VERSION 5.8 ;
BUSBITCHARS "[]" ;
DIVIDERCHAR "/" ;
UNITS
    DATABASE MICRONS 1000 ;
END UNITS

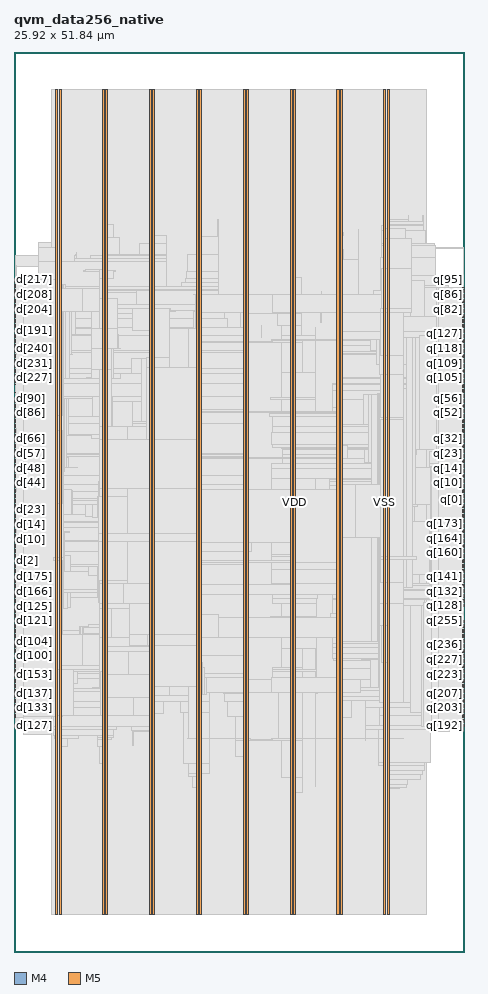
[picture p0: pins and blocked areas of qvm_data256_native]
MACRO qvm_data256_native
  FOREIGN qvm_data256_native 0 0 ;
  CLASS BLOCK ;
  SIZE 25.92 BY 51.84 ;
  PIN clk
    DIRECTION INPUT ;
    USE SIGNAL ;
    PORT
      LAYER M4 ;
        RECT  0 22.704 0.084 22.728 ;
    END
  END clk
  PIN d[0]
    DIRECTION INPUT ;
    USE SIGNAL ;
    PORT
      LAYER M4 ;
        RECT  0 22.8 0.084 22.824 ;
    END
  END d[0]
  PIN d[100]
    DIRECTION INPUT ;
    USE SIGNAL ;
    PORT
      LAYER M4 ;
        RECT  0 17.04 0.084 17.064 ;
    END
  END d[100]
  PIN d[101]
    DIRECTION INPUT ;
    USE SIGNAL ;
    PORT
      LAYER M4 ;
        RECT  0 17.136 0.084 17.16 ;
    END
  END d[101]
  PIN d[102]
    DIRECTION INPUT ;
    USE SIGNAL ;
    PORT
      LAYER M4 ;
        RECT  0 17.232 0.084 17.256 ;
    END
  END d[102]
  PIN d[103]
    DIRECTION INPUT ;
    USE SIGNAL ;
    PORT
      LAYER M4 ;
        RECT  0 17.328 0.084 17.352 ;
    END
  END d[103]
  PIN d[104]
    DIRECTION INPUT ;
    USE SIGNAL ;
    PORT
      LAYER M4 ;
        RECT  0 17.424 0.084 17.448 ;
    END
  END d[104]
  PIN d[105]
    DIRECTION INPUT ;
    USE SIGNAL ;
    PORT
      LAYER M4 ;
        RECT  0 17.52 0.084 17.544 ;
    END
  END d[105]
  PIN d[106]
    DIRECTION INPUT ;
    USE SIGNAL ;
    PORT
      LAYER M4 ;
        RECT  0 17.616 0.084 17.64 ;
    END
  END d[106]
  PIN d[107]
    DIRECTION INPUT ;
    USE SIGNAL ;
    PORT
      LAYER M4 ;
        RECT  0 17.712 0.084 17.736 ;
    END
  END d[107]
  PIN d[108]
    DIRECTION INPUT ;
    USE SIGNAL ;
    PORT
      LAYER M4 ;
        RECT  0 17.808 0.084 17.832 ;
    END
  END d[108]
  PIN d[109]
    DIRECTION INPUT ;
    USE SIGNAL ;
    PORT
      LAYER M4 ;
        RECT  0 17.904 0.084 17.928 ;
    END
  END d[109]
  PIN d[10]
    DIRECTION INPUT ;
    USE SIGNAL ;
    PORT
      LAYER M4 ;
        RECT  0 23.76 0.084 23.784 ;
    END
  END d[10]
  PIN d[110]
    DIRECTION INPUT ;
    USE SIGNAL ;
    PORT
      LAYER M4 ;
        RECT  0 18 0.084 18.024 ;
    END
  END d[110]
  PIN d[111]
    DIRECTION INPUT ;
    USE SIGNAL ;
    PORT
      LAYER M4 ;
        RECT  0 18.096 0.084 18.12 ;
    END
  END d[111]
  PIN d[112]
    DIRECTION INPUT ;
    USE SIGNAL ;
    PORT
      LAYER M4 ;
        RECT  0 18.192 0.084 18.216 ;
    END
  END d[112]
  PIN d[113]
    DIRECTION INPUT ;
    USE SIGNAL ;
    PORT
      LAYER M4 ;
        RECT  0 18.288 0.084 18.312 ;
    END
  END d[113]
  PIN d[114]
    DIRECTION INPUT ;
    USE SIGNAL ;
    PORT
      LAYER M4 ;
        RECT  0 18.384 0.084 18.408 ;
    END
  END d[114]
  PIN d[115]
    DIRECTION INPUT ;
    USE SIGNAL ;
    PORT
      LAYER M4 ;
        RECT  0 18.48 0.084 18.504 ;
    END
  END d[115]
  PIN d[116]
    DIRECTION INPUT ;
    USE SIGNAL ;
    PORT
      LAYER M4 ;
        RECT  0 18.576 0.084 18.6 ;
    END
  END d[116]
  PIN d[117]
    DIRECTION INPUT ;
    USE SIGNAL ;
    PORT
      LAYER M4 ;
        RECT  0 18.672 0.084 18.696 ;
    END
  END d[117]
  PIN d[118]
    DIRECTION INPUT ;
    USE SIGNAL ;
    PORT
      LAYER M4 ;
        RECT  0 18.768 0.084 18.792 ;
    END
  END d[118]
  PIN d[119]
    DIRECTION INPUT ;
    USE SIGNAL ;
    PORT
      LAYER M4 ;
        RECT  0 18.864 0.084 18.888 ;
    END
  END d[119]
  PIN d[11]
    DIRECTION INPUT ;
    USE SIGNAL ;
    PORT
      LAYER M4 ;
        RECT  0 23.856 0.084 23.88 ;
    END
  END d[11]
  PIN d[120]
    DIRECTION INPUT ;
    USE SIGNAL ;
    PORT
      LAYER M4 ;
        RECT  0 18.96 0.084 18.984 ;
    END
  END d[120]
  PIN d[121]
    DIRECTION INPUT ;
    USE SIGNAL ;
    PORT
      LAYER M4 ;
        RECT  0 19.056 0.084 19.08 ;
    END
  END d[121]
  PIN d[122]
    DIRECTION INPUT ;
    USE SIGNAL ;
    PORT
      LAYER M4 ;
        RECT  0 19.152 0.084 19.176 ;
    END
  END d[122]
  PIN d[123]
    DIRECTION INPUT ;
    USE SIGNAL ;
    PORT
      LAYER M4 ;
        RECT  0 19.248 0.084 19.272 ;
    END
  END d[123]
  PIN d[124]
    DIRECTION INPUT ;
    USE SIGNAL ;
    PORT
      LAYER M4 ;
        RECT  0 19.344 0.084 19.368 ;
    END
  END d[124]
  PIN d[125]
    DIRECTION INPUT ;
    USE SIGNAL ;
    PORT
      LAYER M4 ;
        RECT  0 19.44 0.084 19.464 ;
    END
  END d[125]
  PIN d[126]
    DIRECTION INPUT ;
    USE SIGNAL ;
    PORT
      LAYER M4 ;
        RECT  0 19.536 0.084 19.56 ;
    END
  END d[126]
  PIN d[127]
    DIRECTION INPUT ;
    USE SIGNAL ;
    PORT
      LAYER M4 ;
        RECT  0 13.488 0.084 13.512 ;
    END
  END d[127]
  PIN d[128]
    DIRECTION INPUT ;
    USE SIGNAL ;
    PORT
      LAYER M4 ;
        RECT  0 13.584 0.084 13.608 ;
    END
  END d[128]
  PIN d[129]
    DIRECTION INPUT ;
    USE SIGNAL ;
    PORT
      LAYER M4 ;
        RECT  0 13.68 0.084 13.704 ;
    END
  END d[129]
  PIN d[12]
    DIRECTION INPUT ;
    USE SIGNAL ;
    PORT
      LAYER M4 ;
        RECT  0 23.952 0.084 23.976 ;
    END
  END d[12]
  PIN d[130]
    DIRECTION INPUT ;
    USE SIGNAL ;
    PORT
      LAYER M4 ;
        RECT  0 13.776 0.084 13.8 ;
    END
  END d[130]
  PIN d[131]
    DIRECTION INPUT ;
    USE SIGNAL ;
    PORT
      LAYER M4 ;
        RECT  0 13.872 0.084 13.896 ;
    END
  END d[131]
  PIN d[132]
    DIRECTION INPUT ;
    USE SIGNAL ;
    PORT
      LAYER M4 ;
        RECT  0 13.968 0.084 13.992 ;
    END
  END d[132]
  PIN d[133]
    DIRECTION INPUT ;
    USE SIGNAL ;
    PORT
      LAYER M4 ;
        RECT  0 14.064 0.084 14.088 ;
    END
  END d[133]
  PIN d[134]
    DIRECTION INPUT ;
    USE SIGNAL ;
    PORT
      LAYER M4 ;
        RECT  0 14.16 0.084 14.184 ;
    END
  END d[134]
  PIN d[135]
    DIRECTION INPUT ;
    USE SIGNAL ;
    PORT
      LAYER M4 ;
        RECT  0 14.256 0.084 14.28 ;
    END
  END d[135]
  PIN d[136]
    DIRECTION INPUT ;
    USE SIGNAL ;
    PORT
      LAYER M4 ;
        RECT  0 14.352 0.084 14.376 ;
    END
  END d[136]
  PIN d[137]
    DIRECTION INPUT ;
    USE SIGNAL ;
    PORT
      LAYER M4 ;
        RECT  0 14.448 0.084 14.472 ;
    END
  END d[137]
  PIN d[138]
    DIRECTION INPUT ;
    USE SIGNAL ;
    PORT
      LAYER M4 ;
        RECT  0 14.544 0.084 14.568 ;
    END
  END d[138]
  PIN d[139]
    DIRECTION INPUT ;
    USE SIGNAL ;
    PORT
      LAYER M4 ;
        RECT  0 14.64 0.084 14.664 ;
    END
  END d[139]
  PIN d[13]
    DIRECTION INPUT ;
    USE SIGNAL ;
    PORT
      LAYER M4 ;
        RECT  0 24.048 0.084 24.072 ;
    END
  END d[13]
  PIN d[140]
    DIRECTION INPUT ;
    USE SIGNAL ;
    PORT
      LAYER M4 ;
        RECT  0 14.736 0.084 14.76 ;
    END
  END d[140]
  PIN d[141]
    DIRECTION INPUT ;
    USE SIGNAL ;
    PORT
      LAYER M4 ;
        RECT  0 14.832 0.084 14.856 ;
    END
  END d[141]
  PIN d[142]
    DIRECTION INPUT ;
    USE SIGNAL ;
    PORT
      LAYER M4 ;
        RECT  0 14.928 0.084 14.952 ;
    END
  END d[142]
  PIN d[143]
    DIRECTION INPUT ;
    USE SIGNAL ;
    PORT
      LAYER M4 ;
        RECT  0 15.024 0.084 15.048 ;
    END
  END d[143]
  PIN d[144]
    DIRECTION INPUT ;
    USE SIGNAL ;
    PORT
      LAYER M4 ;
        RECT  0 15.12 0.084 15.144 ;
    END
  END d[144]
  PIN d[145]
    DIRECTION INPUT ;
    USE SIGNAL ;
    PORT
      LAYER M4 ;
        RECT  0 15.216 0.084 15.24 ;
    END
  END d[145]
  PIN d[146]
    DIRECTION INPUT ;
    USE SIGNAL ;
    PORT
      LAYER M4 ;
        RECT  0 15.312 0.084 15.336 ;
    END
  END d[146]
  PIN d[147]
    DIRECTION INPUT ;
    USE SIGNAL ;
    PORT
      LAYER M4 ;
        RECT  0 15.408 0.084 15.432 ;
    END
  END d[147]
  PIN d[148]
    DIRECTION INPUT ;
    USE SIGNAL ;
    PORT
      LAYER M4 ;
        RECT  0 15.504 0.084 15.528 ;
    END
  END d[148]
  PIN d[149]
    DIRECTION INPUT ;
    USE SIGNAL ;
    PORT
      LAYER M4 ;
        RECT  0 15.6 0.084 15.624 ;
    END
  END d[149]
  PIN d[14]
    DIRECTION INPUT ;
    USE SIGNAL ;
    PORT
      LAYER M4 ;
        RECT  0 24.144 0.084 24.168 ;
    END
  END d[14]
  PIN d[150]
    DIRECTION INPUT ;
    USE SIGNAL ;
    PORT
      LAYER M4 ;
        RECT  0 15.696 0.084 15.72 ;
    END
  END d[150]
  PIN d[151]
    DIRECTION INPUT ;
    USE SIGNAL ;
    PORT
      LAYER M4 ;
        RECT  0 15.792 0.084 15.816 ;
    END
  END d[151]
  PIN d[152]
    DIRECTION INPUT ;
    USE SIGNAL ;
    PORT
      LAYER M4 ;
        RECT  0 15.888 0.084 15.912 ;
    END
  END d[152]
  PIN d[153]
    DIRECTION INPUT ;
    USE SIGNAL ;
    PORT
      LAYER M4 ;
        RECT  0 15.984 0.084 16.008 ;
    END
  END d[153]
  PIN d[154]
    DIRECTION INPUT ;
    USE SIGNAL ;
    PORT
      LAYER M4 ;
        RECT  0 16.08 0.084 16.104 ;
    END
  END d[154]
  PIN d[155]
    DIRECTION INPUT ;
    USE SIGNAL ;
    PORT
      LAYER M4 ;
        RECT  0 16.176 0.084 16.2 ;
    END
  END d[155]
  PIN d[156]
    DIRECTION INPUT ;
    USE SIGNAL ;
    PORT
      LAYER M4 ;
        RECT  0 16.272 0.084 16.296 ;
    END
  END d[156]
  PIN d[157]
    DIRECTION INPUT ;
    USE SIGNAL ;
    PORT
      LAYER M4 ;
        RECT  0 16.368 0.084 16.392 ;
    END
  END d[157]
  PIN d[158]
    DIRECTION INPUT ;
    USE SIGNAL ;
    PORT
      LAYER M4 ;
        RECT  0 16.464 0.084 16.488 ;
    END
  END d[158]
  PIN d[159]
    DIRECTION INPUT ;
    USE SIGNAL ;
    PORT
      LAYER M4 ;
        RECT  0 19.632 0.084 19.656 ;
    END
  END d[159]
  PIN d[15]
    DIRECTION INPUT ;
    USE SIGNAL ;
    PORT
      LAYER M4 ;
        RECT  0 24.24 0.084 24.264 ;
    END
  END d[15]
  PIN d[160]
    DIRECTION INPUT ;
    USE SIGNAL ;
    PORT
      LAYER M4 ;
        RECT  0 19.728 0.084 19.752 ;
    END
  END d[160]
  PIN d[161]
    DIRECTION INPUT ;
    USE SIGNAL ;
    PORT
      LAYER M4 ;
        RECT  0 19.824 0.084 19.848 ;
    END
  END d[161]
  PIN d[162]
    DIRECTION INPUT ;
    USE SIGNAL ;
    PORT
      LAYER M4 ;
        RECT  0 19.92 0.084 19.944 ;
    END
  END d[162]
  PIN d[163]
    DIRECTION INPUT ;
    USE SIGNAL ;
    PORT
      LAYER M4 ;
        RECT  0 20.016 0.084 20.04 ;
    END
  END d[163]
  PIN d[164]
    DIRECTION INPUT ;
    USE SIGNAL ;
    PORT
      LAYER M4 ;
        RECT  0 20.112 0.084 20.136 ;
    END
  END d[164]
  PIN d[165]
    DIRECTION INPUT ;
    USE SIGNAL ;
    PORT
      LAYER M4 ;
        RECT  0 20.208 0.084 20.232 ;
    END
  END d[165]
  PIN d[166]
    DIRECTION INPUT ;
    USE SIGNAL ;
    PORT
      LAYER M4 ;
        RECT  0 20.304 0.084 20.328 ;
    END
  END d[166]
  PIN d[167]
    DIRECTION INPUT ;
    USE SIGNAL ;
    PORT
      LAYER M4 ;
        RECT  0 20.4 0.084 20.424 ;
    END
  END d[167]
  PIN d[168]
    DIRECTION INPUT ;
    USE SIGNAL ;
    PORT
      LAYER M4 ;
        RECT  0 20.496 0.084 20.52 ;
    END
  END d[168]
  PIN d[169]
    DIRECTION INPUT ;
    USE SIGNAL ;
    PORT
      LAYER M4 ;
        RECT  0 20.592 0.084 20.616 ;
    END
  END d[169]
  PIN d[16]
    DIRECTION INPUT ;
    USE SIGNAL ;
    PORT
      LAYER M4 ;
        RECT  0 24.336 0.084 24.36 ;
    END
  END d[16]
  PIN d[170]
    DIRECTION INPUT ;
    USE SIGNAL ;
    PORT
      LAYER M4 ;
        RECT  0 20.688 0.084 20.712 ;
    END
  END d[170]
  PIN d[171]
    DIRECTION INPUT ;
    USE SIGNAL ;
    PORT
      LAYER M4 ;
        RECT  0 20.784 0.084 20.808 ;
    END
  END d[171]
  PIN d[172]
    DIRECTION INPUT ;
    USE SIGNAL ;
    PORT
      LAYER M4 ;
        RECT  0 20.88 0.084 20.904 ;
    END
  END d[172]
  PIN d[173]
    DIRECTION INPUT ;
    USE SIGNAL ;
    PORT
      LAYER M4 ;
        RECT  0 20.976 0.084 21 ;
    END
  END d[173]
  PIN d[174]
    DIRECTION INPUT ;
    USE SIGNAL ;
    PORT
      LAYER M4 ;
        RECT  0 21.072 0.084 21.096 ;
    END
  END d[174]
  PIN d[175]
    DIRECTION INPUT ;
    USE SIGNAL ;
    PORT
      LAYER M4 ;
        RECT  0 21.168 0.084 21.192 ;
    END
  END d[175]
  PIN d[176]
    DIRECTION INPUT ;
    USE SIGNAL ;
    PORT
      LAYER M4 ;
        RECT  0 21.264 0.084 21.288 ;
    END
  END d[176]
  PIN d[177]
    DIRECTION INPUT ;
    USE SIGNAL ;
    PORT
      LAYER M4 ;
        RECT  0 21.36 0.084 21.384 ;
    END
  END d[177]
  PIN d[178]
    DIRECTION INPUT ;
    USE SIGNAL ;
    PORT
      LAYER M4 ;
        RECT  0 21.456 0.084 21.48 ;
    END
  END d[178]
  PIN d[179]
    DIRECTION INPUT ;
    USE SIGNAL ;
    PORT
      LAYER M4 ;
        RECT  0 21.552 0.084 21.576 ;
    END
  END d[179]
  PIN d[17]
    DIRECTION INPUT ;
    USE SIGNAL ;
    PORT
      LAYER M4 ;
        RECT  0 24.432 0.084 24.456 ;
    END
  END d[17]
  PIN d[180]
    DIRECTION INPUT ;
    USE SIGNAL ;
    PORT
      LAYER M4 ;
        RECT  0 21.648 0.084 21.672 ;
    END
  END d[180]
  PIN d[181]
    DIRECTION INPUT ;
    USE SIGNAL ;
    PORT
      LAYER M4 ;
        RECT  0 21.744 0.084 21.768 ;
    END
  END d[181]
  PIN d[182]
    DIRECTION INPUT ;
    USE SIGNAL ;
    PORT
      LAYER M4 ;
        RECT  0 21.84 0.084 21.864 ;
    END
  END d[182]
  PIN d[183]
    DIRECTION INPUT ;
    USE SIGNAL ;
    PORT
      LAYER M4 ;
        RECT  0 21.936 0.084 21.96 ;
    END
  END d[183]
  PIN d[184]
    DIRECTION INPUT ;
    USE SIGNAL ;
    PORT
      LAYER M4 ;
        RECT  0 22.032 0.084 22.056 ;
    END
  END d[184]
  PIN d[185]
    DIRECTION INPUT ;
    USE SIGNAL ;
    PORT
      LAYER M4 ;
        RECT  0 22.128 0.084 22.152 ;
    END
  END d[185]
  PIN d[186]
    DIRECTION INPUT ;
    USE SIGNAL ;
    PORT
      LAYER M4 ;
        RECT  0 22.224 0.084 22.248 ;
    END
  END d[186]
  PIN d[187]
    DIRECTION INPUT ;
    USE SIGNAL ;
    PORT
      LAYER M4 ;
        RECT  0 22.32 0.084 22.344 ;
    END
  END d[187]
  PIN d[188]
    DIRECTION INPUT ;
    USE SIGNAL ;
    PORT
      LAYER M4 ;
        RECT  0 22.416 0.084 22.44 ;
    END
  END d[188]
  PIN d[189]
    DIRECTION INPUT ;
    USE SIGNAL ;
    PORT
      LAYER M4 ;
        RECT  0 22.512 0.084 22.536 ;
    END
  END d[189]
  PIN d[18]
    DIRECTION INPUT ;
    USE SIGNAL ;
    PORT
      LAYER M4 ;
        RECT  0 24.528 0.084 24.552 ;
    END
  END d[18]
  PIN d[190]
    DIRECTION INPUT ;
    USE SIGNAL ;
    PORT
      LAYER M4 ;
        RECT  0 22.608 0.084 22.632 ;
    END
  END d[190]
  PIN d[191]
    DIRECTION INPUT ;
    USE SIGNAL ;
    PORT
      LAYER M4 ;
        RECT  0 35.76 0.084 35.784 ;
    END
  END d[191]
  PIN d[192]
    DIRECTION INPUT ;
    USE SIGNAL ;
    PORT
      LAYER M4 ;
        RECT  0 35.856 0.084 35.88 ;
    END
  END d[192]
  PIN d[193]
    DIRECTION INPUT ;
    USE SIGNAL ;
    PORT
      LAYER M4 ;
        RECT  0 35.952 0.084 35.976 ;
    END
  END d[193]
  PIN d[194]
    DIRECTION INPUT ;
    USE SIGNAL ;
    PORT
      LAYER M4 ;
        RECT  0 36.048 0.084 36.072 ;
    END
  END d[194]
  PIN d[195]
    DIRECTION INPUT ;
    USE SIGNAL ;
    PORT
      LAYER M4 ;
        RECT  0 36.144 0.084 36.168 ;
    END
  END d[195]
  PIN d[196]
    DIRECTION INPUT ;
    USE SIGNAL ;
    PORT
      LAYER M4 ;
        RECT  0 36.24 0.084 36.264 ;
    END
  END d[196]
  PIN d[197]
    DIRECTION INPUT ;
    USE SIGNAL ;
    PORT
      LAYER M4 ;
        RECT  0 36.336 0.084 36.36 ;
    END
  END d[197]
  PIN d[198]
    DIRECTION INPUT ;
    USE SIGNAL ;
    PORT
      LAYER M4 ;
        RECT  0 36.432 0.084 36.456 ;
    END
  END d[198]
  PIN d[199]
    DIRECTION INPUT ;
    USE SIGNAL ;
    PORT
      LAYER M4 ;
        RECT  0 36.528 0.084 36.552 ;
    END
  END d[199]
  PIN d[19]
    DIRECTION INPUT ;
    USE SIGNAL ;
    PORT
      LAYER M4 ;
        RECT  0 24.624 0.084 24.648 ;
    END
  END d[19]
  PIN d[1]
    DIRECTION INPUT ;
    USE SIGNAL ;
    PORT
      LAYER M4 ;
        RECT  0 22.896 0.084 22.92 ;
    END
  END d[1]
  PIN d[200]
    DIRECTION INPUT ;
    USE SIGNAL ;
    PORT
      LAYER M4 ;
        RECT  0 36.624 0.084 36.648 ;
    END
  END d[200]
  PIN d[201]
    DIRECTION INPUT ;
    USE SIGNAL ;
    PORT
      LAYER M4 ;
        RECT  0 36.72 0.084 36.744 ;
    END
  END d[201]
  PIN d[202]
    DIRECTION INPUT ;
    USE SIGNAL ;
    PORT
      LAYER M4 ;
        RECT  0 36.816 0.084 36.84 ;
    END
  END d[202]
  PIN d[203]
    DIRECTION INPUT ;
    USE SIGNAL ;
    PORT
      LAYER M4 ;
        RECT  0 36.912 0.084 36.936 ;
    END
  END d[203]
  PIN d[204]
    DIRECTION INPUT ;
    USE SIGNAL ;
    PORT
      LAYER M4 ;
        RECT  0 37.008 0.084 37.032 ;
    END
  END d[204]
  PIN d[205]
    DIRECTION INPUT ;
    USE SIGNAL ;
    PORT
      LAYER M4 ;
        RECT  0 37.104 0.084 37.128 ;
    END
  END d[205]
  PIN d[206]
    DIRECTION INPUT ;
    USE SIGNAL ;
    PORT
      LAYER M4 ;
        RECT  0 37.2 0.084 37.224 ;
    END
  END d[206]
  PIN d[207]
    DIRECTION INPUT ;
    USE SIGNAL ;
    PORT
      LAYER M4 ;
        RECT  0 37.296 0.084 37.32 ;
    END
  END d[207]
  PIN d[208]
    DIRECTION INPUT ;
    USE SIGNAL ;
    PORT
      LAYER M4 ;
        RECT  0 37.392 0.084 37.416 ;
    END
  END d[208]
  PIN d[209]
    DIRECTION INPUT ;
    USE SIGNAL ;
    PORT
      LAYER M4 ;
        RECT  0 37.488 0.084 37.512 ;
    END
  END d[209]
  PIN d[20]
    DIRECTION INPUT ;
    USE SIGNAL ;
    PORT
      LAYER M4 ;
        RECT  0 24.72 0.084 24.744 ;
    END
  END d[20]
  PIN d[210]
    DIRECTION INPUT ;
    USE SIGNAL ;
    PORT
      LAYER M4 ;
        RECT  0 37.584 0.084 37.608 ;
    END
  END d[210]
  PIN d[211]
    DIRECTION INPUT ;
    USE SIGNAL ;
    PORT
      LAYER M4 ;
        RECT  0 37.68 0.084 37.704 ;
    END
  END d[211]
  PIN d[212]
    DIRECTION INPUT ;
    USE SIGNAL ;
    PORT
      LAYER M4 ;
        RECT  0 37.776 0.084 37.8 ;
    END
  END d[212]
  PIN d[213]
    DIRECTION INPUT ;
    USE SIGNAL ;
    PORT
      LAYER M4 ;
        RECT  0 37.872 0.084 37.896 ;
    END
  END d[213]
  PIN d[214]
    DIRECTION INPUT ;
    USE SIGNAL ;
    PORT
      LAYER M4 ;
        RECT  0 37.968 0.084 37.992 ;
    END
  END d[214]
  PIN d[215]
    DIRECTION INPUT ;
    USE SIGNAL ;
    PORT
      LAYER M4 ;
        RECT  0 38.064 0.084 38.088 ;
    END
  END d[215]
  PIN d[216]
    DIRECTION INPUT ;
    USE SIGNAL ;
    PORT
      LAYER M4 ;
        RECT  0 38.16 0.084 38.184 ;
    END
  END d[216]
  PIN d[217]
    DIRECTION INPUT ;
    USE SIGNAL ;
    PORT
      LAYER M4 ;
        RECT  0 38.256 0.084 38.28 ;
    END
  END d[217]
  PIN d[218]
    DIRECTION INPUT ;
    USE SIGNAL ;
    PORT
      LAYER M4 ;
        RECT  0 38.352 0.084 38.376 ;
    END
  END d[218]
  PIN d[219]
    DIRECTION INPUT ;
    USE SIGNAL ;
    PORT
      LAYER M4 ;
        RECT  0 38.448 0.084 38.472 ;
    END
  END d[219]
  PIN d[21]
    DIRECTION INPUT ;
    USE SIGNAL ;
    PORT
      LAYER M4 ;
        RECT  0 24.816 0.084 24.84 ;
    END
  END d[21]
  PIN d[220]
    DIRECTION INPUT ;
    USE SIGNAL ;
    PORT
      LAYER M4 ;
        RECT  0 38.544 0.084 38.568 ;
    END
  END d[220]
  PIN d[221]
    DIRECTION INPUT ;
    USE SIGNAL ;
    PORT
      LAYER M4 ;
        RECT  0 38.64 0.084 38.664 ;
    END
  END d[221]
  PIN d[222]
    DIRECTION INPUT ;
    USE SIGNAL ;
    PORT
      LAYER M4 ;
        RECT  0 38.736 0.084 38.76 ;
    END
  END d[222]
  PIN d[223]
    DIRECTION INPUT ;
    USE SIGNAL ;
    PORT
      LAYER M4 ;
        RECT  0 32.688 0.084 32.712 ;
    END
  END d[223]
  PIN d[224]
    DIRECTION INPUT ;
    USE SIGNAL ;
    PORT
      LAYER M4 ;
        RECT  0 32.784 0.084 32.808 ;
    END
  END d[224]
  PIN d[225]
    DIRECTION INPUT ;
    USE SIGNAL ;
    PORT
      LAYER M4 ;
        RECT  0 32.88 0.084 32.904 ;
    END
  END d[225]
  PIN d[226]
    DIRECTION INPUT ;
    USE SIGNAL ;
    PORT
      LAYER M4 ;
        RECT  0 32.976 0.084 33 ;
    END
  END d[226]
  PIN d[227]
    DIRECTION INPUT ;
    USE SIGNAL ;
    PORT
      LAYER M4 ;
        RECT  0 33.072 0.084 33.096 ;
    END
  END d[227]
  PIN d[228]
    DIRECTION INPUT ;
    USE SIGNAL ;
    PORT
      LAYER M4 ;
        RECT  0 33.168 0.084 33.192 ;
    END
  END d[228]
  PIN d[229]
    DIRECTION INPUT ;
    USE SIGNAL ;
    PORT
      LAYER M4 ;
        RECT  0 33.264 0.084 33.288 ;
    END
  END d[229]
  PIN d[22]
    DIRECTION INPUT ;
    USE SIGNAL ;
    PORT
      LAYER M4 ;
        RECT  0 24.912 0.084 24.936 ;
    END
  END d[22]
  PIN d[230]
    DIRECTION INPUT ;
    USE SIGNAL ;
    PORT
      LAYER M4 ;
        RECT  0 33.36 0.084 33.384 ;
    END
  END d[230]
  PIN d[231]
    DIRECTION INPUT ;
    USE SIGNAL ;
    PORT
      LAYER M4 ;
        RECT  0 33.456 0.084 33.48 ;
    END
  END d[231]
  PIN d[232]
    DIRECTION INPUT ;
    USE SIGNAL ;
    PORT
      LAYER M4 ;
        RECT  0 33.552 0.084 33.576 ;
    END
  END d[232]
  PIN d[233]
    DIRECTION INPUT ;
    USE SIGNAL ;
    PORT
      LAYER M4 ;
        RECT  0 33.648 0.084 33.672 ;
    END
  END d[233]
  PIN d[234]
    DIRECTION INPUT ;
    USE SIGNAL ;
    PORT
      LAYER M4 ;
        RECT  0 33.744 0.084 33.768 ;
    END
  END d[234]
  PIN d[235]
    DIRECTION INPUT ;
    USE SIGNAL ;
    PORT
      LAYER M4 ;
        RECT  0 33.84 0.084 33.864 ;
    END
  END d[235]
  PIN d[236]
    DIRECTION INPUT ;
    USE SIGNAL ;
    PORT
      LAYER M4 ;
        RECT  0 33.936 0.084 33.96 ;
    END
  END d[236]
  PIN d[237]
    DIRECTION INPUT ;
    USE SIGNAL ;
    PORT
      LAYER M4 ;
        RECT  0 34.032 0.084 34.056 ;
    END
  END d[237]
  PIN d[238]
    DIRECTION INPUT ;
    USE SIGNAL ;
    PORT
      LAYER M4 ;
        RECT  0 34.128 0.084 34.152 ;
    END
  END d[238]
  PIN d[239]
    DIRECTION INPUT ;
    USE SIGNAL ;
    PORT
      LAYER M4 ;
        RECT  0 34.224 0.084 34.248 ;
    END
  END d[239]
  PIN d[23]
    DIRECTION INPUT ;
    USE SIGNAL ;
    PORT
      LAYER M4 ;
        RECT  0 25.008 0.084 25.032 ;
    END
  END d[23]
  PIN d[240]
    DIRECTION INPUT ;
    USE SIGNAL ;
    PORT
      LAYER M4 ;
        RECT  0 34.32 0.084 34.344 ;
    END
  END d[240]
  PIN d[241]
    DIRECTION INPUT ;
    USE SIGNAL ;
    PORT
      LAYER M4 ;
        RECT  0 34.416 0.084 34.44 ;
    END
  END d[241]
  PIN d[242]
    DIRECTION INPUT ;
    USE SIGNAL ;
    PORT
      LAYER M4 ;
        RECT  0 34.512 0.084 34.536 ;
    END
  END d[242]
  PIN d[243]
    DIRECTION INPUT ;
    USE SIGNAL ;
    PORT
      LAYER M4 ;
        RECT  0 34.608 0.084 34.632 ;
    END
  END d[243]
  PIN d[244]
    DIRECTION INPUT ;
    USE SIGNAL ;
    PORT
      LAYER M4 ;
        RECT  0 34.704 0.084 34.728 ;
    END
  END d[244]
  PIN d[245]
    DIRECTION INPUT ;
    USE SIGNAL ;
    PORT
      LAYER M4 ;
        RECT  0 34.8 0.084 34.824 ;
    END
  END d[245]
  PIN d[246]
    DIRECTION INPUT ;
    USE SIGNAL ;
    PORT
      LAYER M4 ;
        RECT  0 34.896 0.084 34.92 ;
    END
  END d[246]
  PIN d[247]
    DIRECTION INPUT ;
    USE SIGNAL ;
    PORT
      LAYER M4 ;
        RECT  0 34.992 0.084 35.016 ;
    END
  END d[247]
  PIN d[248]
    DIRECTION INPUT ;
    USE SIGNAL ;
    PORT
      LAYER M4 ;
        RECT  0 35.088 0.084 35.112 ;
    END
  END d[248]
  PIN d[249]
    DIRECTION INPUT ;
    USE SIGNAL ;
    PORT
      LAYER M4 ;
        RECT  0 35.184 0.084 35.208 ;
    END
  END d[249]
  PIN d[24]
    DIRECTION INPUT ;
    USE SIGNAL ;
    PORT
      LAYER M4 ;
        RECT  0 25.104 0.084 25.128 ;
    END
  END d[24]
  PIN d[250]
    DIRECTION INPUT ;
    USE SIGNAL ;
    PORT
      LAYER M4 ;
        RECT  0 35.28 0.084 35.304 ;
    END
  END d[250]
  PIN d[251]
    DIRECTION INPUT ;
    USE SIGNAL ;
    PORT
      LAYER M4 ;
        RECT  0 35.376 0.084 35.4 ;
    END
  END d[251]
  PIN d[252]
    DIRECTION INPUT ;
    USE SIGNAL ;
    PORT
      LAYER M4 ;
        RECT  0 35.472 0.084 35.496 ;
    END
  END d[252]
  PIN d[253]
    DIRECTION INPUT ;
    USE SIGNAL ;
    PORT
      LAYER M4 ;
        RECT  0 35.568 0.084 35.592 ;
    END
  END d[253]
  PIN d[254]
    DIRECTION INPUT ;
    USE SIGNAL ;
    PORT
      LAYER M4 ;
        RECT  0 35.664 0.084 35.688 ;
    END
  END d[254]
  PIN d[255]
    DIRECTION INPUT ;
    USE SIGNAL ;
    PORT
      LAYER M4 ;
        RECT  0 32.208 0.084 32.232 ;
    END
  END d[255]
  PIN d[25]
    DIRECTION INPUT ;
    USE SIGNAL ;
    PORT
      LAYER M4 ;
        RECT  0 25.2 0.084 25.224 ;
    END
  END d[25]
  PIN d[26]
    DIRECTION INPUT ;
    USE SIGNAL ;
    PORT
      LAYER M4 ;
        RECT  0 25.296 0.084 25.32 ;
    END
  END d[26]
  PIN d[27]
    DIRECTION INPUT ;
    USE SIGNAL ;
    PORT
      LAYER M4 ;
        RECT  0 25.392 0.084 25.416 ;
    END
  END d[27]
  PIN d[28]
    DIRECTION INPUT ;
    USE SIGNAL ;
    PORT
      LAYER M4 ;
        RECT  0 25.488 0.084 25.512 ;
    END
  END d[28]
  PIN d[29]
    DIRECTION INPUT ;
    USE SIGNAL ;
    PORT
      LAYER M4 ;
        RECT  0 25.584 0.084 25.608 ;
    END
  END d[29]
  PIN d[2]
    DIRECTION INPUT ;
    USE SIGNAL ;
    PORT
      LAYER M4 ;
        RECT  0 22.992 0.084 23.016 ;
    END
  END d[2]
  PIN d[30]
    DIRECTION INPUT ;
    USE SIGNAL ;
    PORT
      LAYER M4 ;
        RECT  0 25.68 0.084 25.704 ;
    END
  END d[30]
  PIN d[31]
    DIRECTION INPUT ;
    USE SIGNAL ;
    PORT
      LAYER M4 ;
        RECT  0 25.776 0.084 25.8 ;
    END
  END d[31]
  PIN d[32]
    DIRECTION INPUT ;
    USE SIGNAL ;
    PORT
      LAYER M4 ;
        RECT  0 25.872 0.084 25.896 ;
    END
  END d[32]
  PIN d[33]
    DIRECTION INPUT ;
    USE SIGNAL ;
    PORT
      LAYER M4 ;
        RECT  0 25.968 0.084 25.992 ;
    END
  END d[33]
  PIN d[34]
    DIRECTION INPUT ;
    USE SIGNAL ;
    PORT
      LAYER M4 ;
        RECT  0 26.064 0.084 26.088 ;
    END
  END d[34]
  PIN d[35]
    DIRECTION INPUT ;
    USE SIGNAL ;
    PORT
      LAYER M4 ;
        RECT  0 26.16 0.084 26.184 ;
    END
  END d[35]
  PIN d[36]
    DIRECTION INPUT ;
    USE SIGNAL ;
    PORT
      LAYER M4 ;
        RECT  0 26.256 0.084 26.28 ;
    END
  END d[36]
  PIN d[37]
    DIRECTION INPUT ;
    USE SIGNAL ;
    PORT
      LAYER M4 ;
        RECT  0 26.352 0.084 26.376 ;
    END
  END d[37]
  PIN d[38]
    DIRECTION INPUT ;
    USE SIGNAL ;
    PORT
      LAYER M4 ;
        RECT  0 26.448 0.084 26.472 ;
    END
  END d[38]
  PIN d[39]
    DIRECTION INPUT ;
    USE SIGNAL ;
    PORT
      LAYER M4 ;
        RECT  0 26.544 0.084 26.568 ;
    END
  END d[39]
  PIN d[3]
    DIRECTION INPUT ;
    USE SIGNAL ;
    PORT
      LAYER M4 ;
        RECT  0 23.088 0.084 23.112 ;
    END
  END d[3]
  PIN d[40]
    DIRECTION INPUT ;
    USE SIGNAL ;
    PORT
      LAYER M4 ;
        RECT  0 26.64 0.084 26.664 ;
    END
  END d[40]
  PIN d[41]
    DIRECTION INPUT ;
    USE SIGNAL ;
    PORT
      LAYER M4 ;
        RECT  0 26.736 0.084 26.76 ;
    END
  END d[41]
  PIN d[42]
    DIRECTION INPUT ;
    USE SIGNAL ;
    PORT
      LAYER M4 ;
        RECT  0 26.832 0.084 26.856 ;
    END
  END d[42]
  PIN d[43]
    DIRECTION INPUT ;
    USE SIGNAL ;
    PORT
      LAYER M4 ;
        RECT  0 26.928 0.084 26.952 ;
    END
  END d[43]
  PIN d[44]
    DIRECTION INPUT ;
    USE SIGNAL ;
    PORT
      LAYER M4 ;
        RECT  0 27.024 0.084 27.048 ;
    END
  END d[44]
  PIN d[45]
    DIRECTION INPUT ;
    USE SIGNAL ;
    PORT
      LAYER M4 ;
        RECT  0 27.12 0.084 27.144 ;
    END
  END d[45]
  PIN d[46]
    DIRECTION INPUT ;
    USE SIGNAL ;
    PORT
      LAYER M4 ;
        RECT  0 27.216 0.084 27.24 ;
    END
  END d[46]
  PIN d[47]
    DIRECTION INPUT ;
    USE SIGNAL ;
    PORT
      LAYER M4 ;
        RECT  0 27.312 0.084 27.336 ;
    END
  END d[47]
  PIN d[48]
    DIRECTION INPUT ;
    USE SIGNAL ;
    PORT
      LAYER M4 ;
        RECT  0 27.408 0.084 27.432 ;
    END
  END d[48]
  PIN d[49]
    DIRECTION INPUT ;
    USE SIGNAL ;
    PORT
      LAYER M4 ;
        RECT  0 27.504 0.084 27.528 ;
    END
  END d[49]
  PIN d[4]
    DIRECTION INPUT ;
    USE SIGNAL ;
    PORT
      LAYER M4 ;
        RECT  0 23.184 0.084 23.208 ;
    END
  END d[4]
  PIN d[50]
    DIRECTION INPUT ;
    USE SIGNAL ;
    PORT
      LAYER M4 ;
        RECT  0 27.6 0.084 27.624 ;
    END
  END d[50]
  PIN d[51]
    DIRECTION INPUT ;
    USE SIGNAL ;
    PORT
      LAYER M4 ;
        RECT  0 27.696 0.084 27.72 ;
    END
  END d[51]
  PIN d[52]
    DIRECTION INPUT ;
    USE SIGNAL ;
    PORT
      LAYER M4 ;
        RECT  0 27.792 0.084 27.816 ;
    END
  END d[52]
  PIN d[53]
    DIRECTION INPUT ;
    USE SIGNAL ;
    PORT
      LAYER M4 ;
        RECT  0 27.888 0.084 27.912 ;
    END
  END d[53]
  PIN d[54]
    DIRECTION INPUT ;
    USE SIGNAL ;
    PORT
      LAYER M4 ;
        RECT  0 27.984 0.084 28.008 ;
    END
  END d[54]
  PIN d[55]
    DIRECTION INPUT ;
    USE SIGNAL ;
    PORT
      LAYER M4 ;
        RECT  0 28.08 0.084 28.104 ;
    END
  END d[55]
  PIN d[56]
    DIRECTION INPUT ;
    USE SIGNAL ;
    PORT
      LAYER M4 ;
        RECT  0 28.176 0.084 28.2 ;
    END
  END d[56]
  PIN d[57]
    DIRECTION INPUT ;
    USE SIGNAL ;
    PORT
      LAYER M4 ;
        RECT  0 28.272 0.084 28.296 ;
    END
  END d[57]
  PIN d[58]
    DIRECTION INPUT ;
    USE SIGNAL ;
    PORT
      LAYER M4 ;
        RECT  0 28.368 0.084 28.392 ;
    END
  END d[58]
  PIN d[59]
    DIRECTION INPUT ;
    USE SIGNAL ;
    PORT
      LAYER M4 ;
        RECT  0 28.464 0.084 28.488 ;
    END
  END d[59]
  PIN d[5]
    DIRECTION INPUT ;
    USE SIGNAL ;
    PORT
      LAYER M4 ;
        RECT  0 23.28 0.084 23.304 ;
    END
  END d[5]
  PIN d[60]
    DIRECTION INPUT ;
    USE SIGNAL ;
    PORT
      LAYER M4 ;
        RECT  0 28.56 0.084 28.584 ;
    END
  END d[60]
  PIN d[61]
    DIRECTION INPUT ;
    USE SIGNAL ;
    PORT
      LAYER M4 ;
        RECT  0 28.656 0.084 28.68 ;
    END
  END d[61]
  PIN d[62]
    DIRECTION INPUT ;
    USE SIGNAL ;
    PORT
      LAYER M4 ;
        RECT  0 28.752 0.084 28.776 ;
    END
  END d[62]
  PIN d[63]
    DIRECTION INPUT ;
    USE SIGNAL ;
    PORT
      LAYER M4 ;
        RECT  0 28.848 0.084 28.872 ;
    END
  END d[63]
  PIN d[64]
    DIRECTION INPUT ;
    USE SIGNAL ;
    PORT
      LAYER M4 ;
        RECT  0 28.944 0.084 28.968 ;
    END
  END d[64]
  PIN d[65]
    DIRECTION INPUT ;
    USE SIGNAL ;
    PORT
      LAYER M4 ;
        RECT  0 29.04 0.084 29.064 ;
    END
  END d[65]
  PIN d[66]
    DIRECTION INPUT ;
    USE SIGNAL ;
    PORT
      LAYER M4 ;
        RECT  0 29.136 0.084 29.16 ;
    END
  END d[66]
  PIN d[67]
    DIRECTION INPUT ;
    USE SIGNAL ;
    PORT
      LAYER M4 ;
        RECT  0 29.232 0.084 29.256 ;
    END
  END d[67]
  PIN d[68]
    DIRECTION INPUT ;
    USE SIGNAL ;
    PORT
      LAYER M4 ;
        RECT  0 29.328 0.084 29.352 ;
    END
  END d[68]
  PIN d[69]
    DIRECTION INPUT ;
    USE SIGNAL ;
    PORT
      LAYER M4 ;
        RECT  0 29.424 0.084 29.448 ;
    END
  END d[69]
  PIN d[6]
    DIRECTION INPUT ;
    USE SIGNAL ;
    PORT
      LAYER M4 ;
        RECT  0 23.376 0.084 23.4 ;
    END
  END d[6]
  PIN d[70]
    DIRECTION INPUT ;
    USE SIGNAL ;
    PORT
      LAYER M4 ;
        RECT  0 29.52 0.084 29.544 ;
    END
  END d[70]
  PIN d[71]
    DIRECTION INPUT ;
    USE SIGNAL ;
    PORT
      LAYER M4 ;
        RECT  0 29.616 0.084 29.64 ;
    END
  END d[71]
  PIN d[72]
    DIRECTION INPUT ;
    USE SIGNAL ;
    PORT
      LAYER M4 ;
        RECT  0 29.712 0.084 29.736 ;
    END
  END d[72]
  PIN d[73]
    DIRECTION INPUT ;
    USE SIGNAL ;
    PORT
      LAYER M4 ;
        RECT  0 29.808 0.084 29.832 ;
    END
  END d[73]
  PIN d[74]
    DIRECTION INPUT ;
    USE SIGNAL ;
    PORT
      LAYER M4 ;
        RECT  0 29.904 0.084 29.928 ;
    END
  END d[74]
  PIN d[75]
    DIRECTION INPUT ;
    USE SIGNAL ;
    PORT
      LAYER M4 ;
        RECT  0 30 0.084 30.024 ;
    END
  END d[75]
  PIN d[76]
    DIRECTION INPUT ;
    USE SIGNAL ;
    PORT
      LAYER M4 ;
        RECT  0 30.096 0.084 30.12 ;
    END
  END d[76]
  PIN d[77]
    DIRECTION INPUT ;
    USE SIGNAL ;
    PORT
      LAYER M4 ;
        RECT  0 30.192 0.084 30.216 ;
    END
  END d[77]
  PIN d[78]
    DIRECTION INPUT ;
    USE SIGNAL ;
    PORT
      LAYER M4 ;
        RECT  0 30.288 0.084 30.312 ;
    END
  END d[78]
  PIN d[79]
    DIRECTION INPUT ;
    USE SIGNAL ;
    PORT
      LAYER M4 ;
        RECT  0 30.384 0.084 30.408 ;
    END
  END d[79]
  PIN d[7]
    DIRECTION INPUT ;
    USE SIGNAL ;
    PORT
      LAYER M4 ;
        RECT  0 23.472 0.084 23.496 ;
    END
  END d[7]
  PIN d[80]
    DIRECTION INPUT ;
    USE SIGNAL ;
    PORT
      LAYER M4 ;
        RECT  0 30.48 0.084 30.504 ;
    END
  END d[80]
  PIN d[81]
    DIRECTION INPUT ;
    USE SIGNAL ;
    PORT
      LAYER M4 ;
        RECT  0 30.576 0.084 30.6 ;
    END
  END d[81]
  PIN d[82]
    DIRECTION INPUT ;
    USE SIGNAL ;
    PORT
      LAYER M4 ;
        RECT  0 30.672 0.084 30.696 ;
    END
  END d[82]
  PIN d[83]
    DIRECTION INPUT ;
    USE SIGNAL ;
    PORT
      LAYER M4 ;
        RECT  0 30.768 0.084 30.792 ;
    END
  END d[83]
  PIN d[84]
    DIRECTION INPUT ;
    USE SIGNAL ;
    PORT
      LAYER M4 ;
        RECT  0 30.864 0.084 30.888 ;
    END
  END d[84]
  PIN d[85]
    DIRECTION INPUT ;
    USE SIGNAL ;
    PORT
      LAYER M4 ;
        RECT  0 30.96 0.084 30.984 ;
    END
  END d[85]
  PIN d[86]
    DIRECTION INPUT ;
    USE SIGNAL ;
    PORT
      LAYER M4 ;
        RECT  0 31.056 0.084 31.08 ;
    END
  END d[86]
  PIN d[87]
    DIRECTION INPUT ;
    USE SIGNAL ;
    PORT
      LAYER M4 ;
        RECT  0 31.152 0.084 31.176 ;
    END
  END d[87]
  PIN d[88]
    DIRECTION INPUT ;
    USE SIGNAL ;
    PORT
      LAYER M4 ;
        RECT  0 31.248 0.084 31.272 ;
    END
  END d[88]
  PIN d[89]
    DIRECTION INPUT ;
    USE SIGNAL ;
    PORT
      LAYER M4 ;
        RECT  0 31.344 0.084 31.368 ;
    END
  END d[89]
  PIN d[8]
    DIRECTION INPUT ;
    USE SIGNAL ;
    PORT
      LAYER M4 ;
        RECT  0 23.568 0.084 23.592 ;
    END
  END d[8]
  PIN d[90]
    DIRECTION INPUT ;
    USE SIGNAL ;
    PORT
      LAYER M4 ;
        RECT  0 31.44 0.084 31.464 ;
    END
  END d[90]
  PIN d[91]
    DIRECTION INPUT ;
    USE SIGNAL ;
    PORT
      LAYER M4 ;
        RECT  0 31.536 0.084 31.56 ;
    END
  END d[91]
  PIN d[92]
    DIRECTION INPUT ;
    USE SIGNAL ;
    PORT
      LAYER M4 ;
        RECT  0 31.632 0.084 31.656 ;
    END
  END d[92]
  PIN d[93]
    DIRECTION INPUT ;
    USE SIGNAL ;
    PORT
      LAYER M4 ;
        RECT  0 31.728 0.084 31.752 ;
    END
  END d[93]
  PIN d[94]
    DIRECTION INPUT ;
    USE SIGNAL ;
    PORT
      LAYER M4 ;
        RECT  0 31.824 0.084 31.848 ;
    END
  END d[94]
  PIN d[95]
    DIRECTION INPUT ;
    USE SIGNAL ;
    PORT
      LAYER M4 ;
        RECT  0 16.56 0.084 16.584 ;
    END
  END d[95]
  PIN d[96]
    DIRECTION INPUT ;
    USE SIGNAL ;
    PORT
      LAYER M4 ;
        RECT  0 16.656 0.084 16.68 ;
    END
  END d[96]
  PIN d[97]
    DIRECTION INPUT ;
    USE SIGNAL ;
    PORT
      LAYER M4 ;
        RECT  0 16.752 0.084 16.776 ;
    END
  END d[97]
  PIN d[98]
    DIRECTION INPUT ;
    USE SIGNAL ;
    PORT
      LAYER M4 ;
        RECT  0 16.848 0.084 16.872 ;
    END
  END d[98]
  PIN d[99]
    DIRECTION INPUT ;
    USE SIGNAL ;
    PORT
      LAYER M4 ;
        RECT  0 16.944 0.084 16.968 ;
    END
  END d[99]
  PIN d[9]
    DIRECTION INPUT ;
    USE SIGNAL ;
    PORT
      LAYER M4 ;
        RECT  0 23.664 0.084 23.688 ;
    END
  END d[9]
  PIN q[0]
    DIRECTION OUTPUT ;
    USE SIGNAL ;
    PORT
      LAYER M4 ;
        RECT  25.836 26.064 25.92 26.088 ;
    END
  END q[0]
  PIN q[100]
    DIRECTION OUTPUT ;
    USE SIGNAL ;
    PORT
      LAYER M4 ;
        RECT  25.836 32.592 25.92 32.616 ;
    END
  END q[100]
  PIN q[101]
    DIRECTION OUTPUT ;
    USE SIGNAL ;
    PORT
      LAYER M4 ;
        RECT  25.836 32.688 25.92 32.712 ;
    END
  END q[101]
  PIN q[102]
    DIRECTION OUTPUT ;
    USE SIGNAL ;
    PORT
      LAYER M4 ;
        RECT  25.836 32.784 25.92 32.808 ;
    END
  END q[102]
  PIN q[103]
    DIRECTION OUTPUT ;
    USE SIGNAL ;
    PORT
      LAYER M4 ;
        RECT  25.836 32.88 25.92 32.904 ;
    END
  END q[103]
  PIN q[104]
    DIRECTION OUTPUT ;
    USE SIGNAL ;
    PORT
      LAYER M4 ;
        RECT  25.836 32.976 25.92 33 ;
    END
  END q[104]
  PIN q[105]
    DIRECTION OUTPUT ;
    USE SIGNAL ;
    PORT
      LAYER M4 ;
        RECT  25.836 33.072 25.92 33.096 ;
    END
  END q[105]
  PIN q[106]
    DIRECTION OUTPUT ;
    USE SIGNAL ;
    PORT
      LAYER M4 ;
        RECT  25.836 33.168 25.92 33.192 ;
    END
  END q[106]
  PIN q[107]
    DIRECTION OUTPUT ;
    USE SIGNAL ;
    PORT
      LAYER M4 ;
        RECT  25.836 33.264 25.92 33.288 ;
    END
  END q[107]
  PIN q[108]
    DIRECTION OUTPUT ;
    USE SIGNAL ;
    PORT
      LAYER M4 ;
        RECT  25.836 33.36 25.92 33.384 ;
    END
  END q[108]
  PIN q[109]
    DIRECTION OUTPUT ;
    USE SIGNAL ;
    PORT
      LAYER M4 ;
        RECT  25.836 33.456 25.92 33.48 ;
    END
  END q[109]
  PIN q[10]
    DIRECTION OUTPUT ;
    USE SIGNAL ;
    PORT
      LAYER M4 ;
        RECT  25.836 27.024 25.92 27.048 ;
    END
  END q[10]
  PIN q[110]
    DIRECTION OUTPUT ;
    USE SIGNAL ;
    PORT
      LAYER M4 ;
        RECT  25.836 33.552 25.92 33.576 ;
    END
  END q[110]
  PIN q[111]
    DIRECTION OUTPUT ;
    USE SIGNAL ;
    PORT
      LAYER M4 ;
        RECT  25.836 33.648 25.92 33.672 ;
    END
  END q[111]
  PIN q[112]
    DIRECTION OUTPUT ;
    USE SIGNAL ;
    PORT
      LAYER M4 ;
        RECT  25.836 33.744 25.92 33.768 ;
    END
  END q[112]
  PIN q[113]
    DIRECTION OUTPUT ;
    USE SIGNAL ;
    PORT
      LAYER M4 ;
        RECT  25.836 33.84 25.92 33.864 ;
    END
  END q[113]
  PIN q[114]
    DIRECTION OUTPUT ;
    USE SIGNAL ;
    PORT
      LAYER M4 ;
        RECT  25.836 33.936 25.92 33.96 ;
    END
  END q[114]
  PIN q[115]
    DIRECTION OUTPUT ;
    USE SIGNAL ;
    PORT
      LAYER M4 ;
        RECT  25.836 34.032 25.92 34.056 ;
    END
  END q[115]
  PIN q[116]
    DIRECTION OUTPUT ;
    USE SIGNAL ;
    PORT
      LAYER M4 ;
        RECT  25.836 34.128 25.92 34.152 ;
    END
  END q[116]
  PIN q[117]
    DIRECTION OUTPUT ;
    USE SIGNAL ;
    PORT
      LAYER M4 ;
        RECT  25.836 34.224 25.92 34.248 ;
    END
  END q[117]
  PIN q[118]
    DIRECTION OUTPUT ;
    USE SIGNAL ;
    PORT
      LAYER M4 ;
        RECT  25.836 34.32 25.92 34.344 ;
    END
  END q[118]
  PIN q[119]
    DIRECTION OUTPUT ;
    USE SIGNAL ;
    PORT
      LAYER M4 ;
        RECT  25.836 34.416 25.92 34.44 ;
    END
  END q[119]
  PIN q[11]
    DIRECTION OUTPUT ;
    USE SIGNAL ;
    PORT
      LAYER M4 ;
        RECT  25.836 27.12 25.92 27.144 ;
    END
  END q[11]
  PIN q[120]
    DIRECTION OUTPUT ;
    USE SIGNAL ;
    PORT
      LAYER M4 ;
        RECT  25.836 34.512 25.92 34.536 ;
    END
  END q[120]
  PIN q[121]
    DIRECTION OUTPUT ;
    USE SIGNAL ;
    PORT
      LAYER M4 ;
        RECT  25.836 34.608 25.92 34.632 ;
    END
  END q[121]
  PIN q[122]
    DIRECTION OUTPUT ;
    USE SIGNAL ;
    PORT
      LAYER M4 ;
        RECT  25.836 34.704 25.92 34.728 ;
    END
  END q[122]
  PIN q[123]
    DIRECTION OUTPUT ;
    USE SIGNAL ;
    PORT
      LAYER M4 ;
        RECT  25.836 34.8 25.92 34.824 ;
    END
  END q[123]
  PIN q[124]
    DIRECTION OUTPUT ;
    USE SIGNAL ;
    PORT
      LAYER M4 ;
        RECT  25.836 34.896 25.92 34.92 ;
    END
  END q[124]
  PIN q[125]
    DIRECTION OUTPUT ;
    USE SIGNAL ;
    PORT
      LAYER M4 ;
        RECT  25.836 34.992 25.92 35.016 ;
    END
  END q[125]
  PIN q[126]
    DIRECTION OUTPUT ;
    USE SIGNAL ;
    PORT
      LAYER M4 ;
        RECT  25.836 35.088 25.92 35.112 ;
    END
  END q[126]
  PIN q[127]
    DIRECTION OUTPUT ;
    USE SIGNAL ;
    PORT
      LAYER M4 ;
        RECT  25.836 35.184 25.92 35.208 ;
    END
  END q[127]
  PIN q[128]
    DIRECTION OUTPUT ;
    USE SIGNAL ;
    PORT
      LAYER M4 ;
        RECT  25.836 19.92 25.92 19.944 ;
    END
  END q[128]
  PIN q[129]
    DIRECTION OUTPUT ;
    USE SIGNAL ;
    PORT
      LAYER M4 ;
        RECT  25.836 20.016 25.92 20.04 ;
    END
  END q[129]
  PIN q[12]
    DIRECTION OUTPUT ;
    USE SIGNAL ;
    PORT
      LAYER M4 ;
        RECT  25.836 27.216 25.92 27.24 ;
    END
  END q[12]
  PIN q[130]
    DIRECTION OUTPUT ;
    USE SIGNAL ;
    PORT
      LAYER M4 ;
        RECT  25.836 20.112 25.92 20.136 ;
    END
  END q[130]
  PIN q[131]
    DIRECTION OUTPUT ;
    USE SIGNAL ;
    PORT
      LAYER M4 ;
        RECT  25.836 20.208 25.92 20.232 ;
    END
  END q[131]
  PIN q[132]
    DIRECTION OUTPUT ;
    USE SIGNAL ;
    PORT
      LAYER M4 ;
        RECT  25.836 20.304 25.92 20.328 ;
    END
  END q[132]
  PIN q[133]
    DIRECTION OUTPUT ;
    USE SIGNAL ;
    PORT
      LAYER M4 ;
        RECT  25.836 20.4 25.92 20.424 ;
    END
  END q[133]
  PIN q[134]
    DIRECTION OUTPUT ;
    USE SIGNAL ;
    PORT
      LAYER M4 ;
        RECT  25.836 20.496 25.92 20.52 ;
    END
  END q[134]
  PIN q[135]
    DIRECTION OUTPUT ;
    USE SIGNAL ;
    PORT
      LAYER M4 ;
        RECT  25.836 20.592 25.92 20.616 ;
    END
  END q[135]
  PIN q[136]
    DIRECTION OUTPUT ;
    USE SIGNAL ;
    PORT
      LAYER M4 ;
        RECT  25.836 20.688 25.92 20.712 ;
    END
  END q[136]
  PIN q[137]
    DIRECTION OUTPUT ;
    USE SIGNAL ;
    PORT
      LAYER M4 ;
        RECT  25.836 20.784 25.92 20.808 ;
    END
  END q[137]
  PIN q[138]
    DIRECTION OUTPUT ;
    USE SIGNAL ;
    PORT
      LAYER M4 ;
        RECT  25.836 20.88 25.92 20.904 ;
    END
  END q[138]
  PIN q[139]
    DIRECTION OUTPUT ;
    USE SIGNAL ;
    PORT
      LAYER M4 ;
        RECT  25.836 20.976 25.92 21 ;
    END
  END q[139]
  PIN q[13]
    DIRECTION OUTPUT ;
    USE SIGNAL ;
    PORT
      LAYER M4 ;
        RECT  25.836 27.312 25.92 27.336 ;
    END
  END q[13]
  PIN q[140]
    DIRECTION OUTPUT ;
    USE SIGNAL ;
    PORT
      LAYER M4 ;
        RECT  25.836 21.072 25.92 21.096 ;
    END
  END q[140]
  PIN q[141]
    DIRECTION OUTPUT ;
    USE SIGNAL ;
    PORT
      LAYER M4 ;
        RECT  25.836 21.168 25.92 21.192 ;
    END
  END q[141]
  PIN q[142]
    DIRECTION OUTPUT ;
    USE SIGNAL ;
    PORT
      LAYER M4 ;
        RECT  25.836 21.264 25.92 21.288 ;
    END
  END q[142]
  PIN q[143]
    DIRECTION OUTPUT ;
    USE SIGNAL ;
    PORT
      LAYER M4 ;
        RECT  25.836 21.36 25.92 21.384 ;
    END
  END q[143]
  PIN q[144]
    DIRECTION OUTPUT ;
    USE SIGNAL ;
    PORT
      LAYER M4 ;
        RECT  25.836 21.456 25.92 21.48 ;
    END
  END q[144]
  PIN q[145]
    DIRECTION OUTPUT ;
    USE SIGNAL ;
    PORT
      LAYER M4 ;
        RECT  25.836 21.552 25.92 21.576 ;
    END
  END q[145]
  PIN q[146]
    DIRECTION OUTPUT ;
    USE SIGNAL ;
    PORT
      LAYER M4 ;
        RECT  25.836 21.648 25.92 21.672 ;
    END
  END q[146]
  PIN q[147]
    DIRECTION OUTPUT ;
    USE SIGNAL ;
    PORT
      LAYER M4 ;
        RECT  25.836 21.744 25.92 21.768 ;
    END
  END q[147]
  PIN q[148]
    DIRECTION OUTPUT ;
    USE SIGNAL ;
    PORT
      LAYER M4 ;
        RECT  25.836 21.84 25.92 21.864 ;
    END
  END q[148]
  PIN q[149]
    DIRECTION OUTPUT ;
    USE SIGNAL ;
    PORT
      LAYER M4 ;
        RECT  25.836 21.936 25.92 21.96 ;
    END
  END q[149]
  PIN q[14]
    DIRECTION OUTPUT ;
    USE SIGNAL ;
    PORT
      LAYER M4 ;
        RECT  25.836 27.408 25.92 27.432 ;
    END
  END q[14]
  PIN q[150]
    DIRECTION OUTPUT ;
    USE SIGNAL ;
    PORT
      LAYER M4 ;
        RECT  25.836 22.032 25.92 22.056 ;
    END
  END q[150]
  PIN q[151]
    DIRECTION OUTPUT ;
    USE SIGNAL ;
    PORT
      LAYER M4 ;
        RECT  25.836 22.128 25.92 22.152 ;
    END
  END q[151]
  PIN q[152]
    DIRECTION OUTPUT ;
    USE SIGNAL ;
    PORT
      LAYER M4 ;
        RECT  25.836 22.224 25.92 22.248 ;
    END
  END q[152]
  PIN q[153]
    DIRECTION OUTPUT ;
    USE SIGNAL ;
    PORT
      LAYER M4 ;
        RECT  25.836 22.32 25.92 22.344 ;
    END
  END q[153]
  PIN q[154]
    DIRECTION OUTPUT ;
    USE SIGNAL ;
    PORT
      LAYER M4 ;
        RECT  25.836 22.416 25.92 22.44 ;
    END
  END q[154]
  PIN q[155]
    DIRECTION OUTPUT ;
    USE SIGNAL ;
    PORT
      LAYER M4 ;
        RECT  25.836 22.512 25.92 22.536 ;
    END
  END q[155]
  PIN q[156]
    DIRECTION OUTPUT ;
    USE SIGNAL ;
    PORT
      LAYER M4 ;
        RECT  25.836 22.608 25.92 22.632 ;
    END
  END q[156]
  PIN q[157]
    DIRECTION OUTPUT ;
    USE SIGNAL ;
    PORT
      LAYER M4 ;
        RECT  25.836 22.704 25.92 22.728 ;
    END
  END q[157]
  PIN q[158]
    DIRECTION OUTPUT ;
    USE SIGNAL ;
    PORT
      LAYER M4 ;
        RECT  25.836 22.8 25.92 22.824 ;
    END
  END q[158]
  PIN q[159]
    DIRECTION OUTPUT ;
    USE SIGNAL ;
    PORT
      LAYER M4 ;
        RECT  25.836 22.896 25.92 22.92 ;
    END
  END q[159]
  PIN q[15]
    DIRECTION OUTPUT ;
    USE SIGNAL ;
    PORT
      LAYER M4 ;
        RECT  25.836 27.504 25.92 27.528 ;
    END
  END q[15]
  PIN q[160]
    DIRECTION OUTPUT ;
    USE SIGNAL ;
    PORT
      LAYER M4 ;
        RECT  25.836 22.992 25.92 23.016 ;
    END
  END q[160]
  PIN q[161]
    DIRECTION OUTPUT ;
    USE SIGNAL ;
    PORT
      LAYER M4 ;
        RECT  25.836 23.088 25.92 23.112 ;
    END
  END q[161]
  PIN q[162]
    DIRECTION OUTPUT ;
    USE SIGNAL ;
    PORT
      LAYER M4 ;
        RECT  25.836 23.184 25.92 23.208 ;
    END
  END q[162]
  PIN q[163]
    DIRECTION OUTPUT ;
    USE SIGNAL ;
    PORT
      LAYER M4 ;
        RECT  25.836 23.28 25.92 23.304 ;
    END
  END q[163]
  PIN q[164]
    DIRECTION OUTPUT ;
    USE SIGNAL ;
    PORT
      LAYER M4 ;
        RECT  25.836 23.376 25.92 23.4 ;
    END
  END q[164]
  PIN q[165]
    DIRECTION OUTPUT ;
    USE SIGNAL ;
    PORT
      LAYER M4 ;
        RECT  25.836 23.472 25.92 23.496 ;
    END
  END q[165]
  PIN q[166]
    DIRECTION OUTPUT ;
    USE SIGNAL ;
    PORT
      LAYER M4 ;
        RECT  25.836 23.568 25.92 23.592 ;
    END
  END q[166]
  PIN q[167]
    DIRECTION OUTPUT ;
    USE SIGNAL ;
    PORT
      LAYER M4 ;
        RECT  25.836 23.664 25.92 23.688 ;
    END
  END q[167]
  PIN q[168]
    DIRECTION OUTPUT ;
    USE SIGNAL ;
    PORT
      LAYER M4 ;
        RECT  25.836 23.76 25.92 23.784 ;
    END
  END q[168]
  PIN q[169]
    DIRECTION OUTPUT ;
    USE SIGNAL ;
    PORT
      LAYER M4 ;
        RECT  25.836 23.856 25.92 23.88 ;
    END
  END q[169]
  PIN q[16]
    DIRECTION OUTPUT ;
    USE SIGNAL ;
    PORT
      LAYER M4 ;
        RECT  25.836 27.6 25.92 27.624 ;
    END
  END q[16]
  PIN q[170]
    DIRECTION OUTPUT ;
    USE SIGNAL ;
    PORT
      LAYER M4 ;
        RECT  25.836 23.952 25.92 23.976 ;
    END
  END q[170]
  PIN q[171]
    DIRECTION OUTPUT ;
    USE SIGNAL ;
    PORT
      LAYER M4 ;
        RECT  25.836 24.048 25.92 24.072 ;
    END
  END q[171]
  PIN q[172]
    DIRECTION OUTPUT ;
    USE SIGNAL ;
    PORT
      LAYER M4 ;
        RECT  25.836 24.144 25.92 24.168 ;
    END
  END q[172]
  PIN q[173]
    DIRECTION OUTPUT ;
    USE SIGNAL ;
    PORT
      LAYER M4 ;
        RECT  25.836 24.24 25.92 24.264 ;
    END
  END q[173]
  PIN q[174]
    DIRECTION OUTPUT ;
    USE SIGNAL ;
    PORT
      LAYER M4 ;
        RECT  25.836 24.336 25.92 24.36 ;
    END
  END q[174]
  PIN q[175]
    DIRECTION OUTPUT ;
    USE SIGNAL ;
    PORT
      LAYER M4 ;
        RECT  25.836 24.432 25.92 24.456 ;
    END
  END q[175]
  PIN q[176]
    DIRECTION OUTPUT ;
    USE SIGNAL ;
    PORT
      LAYER M4 ;
        RECT  25.836 24.528 25.92 24.552 ;
    END
  END q[176]
  PIN q[177]
    DIRECTION OUTPUT ;
    USE SIGNAL ;
    PORT
      LAYER M4 ;
        RECT  25.836 24.624 25.92 24.648 ;
    END
  END q[177]
  PIN q[178]
    DIRECTION OUTPUT ;
    USE SIGNAL ;
    PORT
      LAYER M4 ;
        RECT  25.836 24.72 25.92 24.744 ;
    END
  END q[178]
  PIN q[179]
    DIRECTION OUTPUT ;
    USE SIGNAL ;
    PORT
      LAYER M4 ;
        RECT  25.836 24.816 25.92 24.84 ;
    END
  END q[179]
  PIN q[17]
    DIRECTION OUTPUT ;
    USE SIGNAL ;
    PORT
      LAYER M4 ;
        RECT  25.836 27.696 25.92 27.72 ;
    END
  END q[17]
  PIN q[180]
    DIRECTION OUTPUT ;
    USE SIGNAL ;
    PORT
      LAYER M4 ;
        RECT  25.836 24.912 25.92 24.936 ;
    END
  END q[180]
  PIN q[181]
    DIRECTION OUTPUT ;
    USE SIGNAL ;
    PORT
      LAYER M4 ;
        RECT  25.836 25.008 25.92 25.032 ;
    END
  END q[181]
  PIN q[182]
    DIRECTION OUTPUT ;
    USE SIGNAL ;
    PORT
      LAYER M4 ;
        RECT  25.836 25.104 25.92 25.128 ;
    END
  END q[182]
  PIN q[183]
    DIRECTION OUTPUT ;
    USE SIGNAL ;
    PORT
      LAYER M4 ;
        RECT  25.836 25.2 25.92 25.224 ;
    END
  END q[183]
  PIN q[184]
    DIRECTION OUTPUT ;
    USE SIGNAL ;
    PORT
      LAYER M4 ;
        RECT  25.836 25.296 25.92 25.32 ;
    END
  END q[184]
  PIN q[185]
    DIRECTION OUTPUT ;
    USE SIGNAL ;
    PORT
      LAYER M4 ;
        RECT  25.836 25.392 25.92 25.416 ;
    END
  END q[185]
  PIN q[186]
    DIRECTION OUTPUT ;
    USE SIGNAL ;
    PORT
      LAYER M4 ;
        RECT  25.836 25.488 25.92 25.512 ;
    END
  END q[186]
  PIN q[187]
    DIRECTION OUTPUT ;
    USE SIGNAL ;
    PORT
      LAYER M4 ;
        RECT  25.836 25.584 25.92 25.608 ;
    END
  END q[187]
  PIN q[188]
    DIRECTION OUTPUT ;
    USE SIGNAL ;
    PORT
      LAYER M4 ;
        RECT  25.836 25.68 25.92 25.704 ;
    END
  END q[188]
  PIN q[189]
    DIRECTION OUTPUT ;
    USE SIGNAL ;
    PORT
      LAYER M4 ;
        RECT  25.836 25.776 25.92 25.8 ;
    END
  END q[189]
  PIN q[18]
    DIRECTION OUTPUT ;
    USE SIGNAL ;
    PORT
      LAYER M4 ;
        RECT  25.836 27.792 25.92 27.816 ;
    END
  END q[18]
  PIN q[190]
    DIRECTION OUTPUT ;
    USE SIGNAL ;
    PORT
      LAYER M4 ;
        RECT  25.836 25.872 25.92 25.896 ;
    END
  END q[190]
  PIN q[191]
    DIRECTION OUTPUT ;
    USE SIGNAL ;
    PORT
      LAYER M4 ;
        RECT  25.836 25.968 25.92 25.992 ;
    END
  END q[191]
  PIN q[192]
    DIRECTION OUTPUT ;
    USE SIGNAL ;
    PORT
      LAYER M4 ;
        RECT  25.836 13.008 25.92 13.032 ;
    END
  END q[192]
  PIN q[193]
    DIRECTION OUTPUT ;
    USE SIGNAL ;
    PORT
      LAYER M4 ;
        RECT  25.836 13.104 25.92 13.128 ;
    END
  END q[193]
  PIN q[194]
    DIRECTION OUTPUT ;
    USE SIGNAL ;
    PORT
      LAYER M4 ;
        RECT  25.836 13.2 25.92 13.224 ;
    END
  END q[194]
  PIN q[195]
    DIRECTION OUTPUT ;
    USE SIGNAL ;
    PORT
      LAYER M4 ;
        RECT  25.836 13.296 25.92 13.32 ;
    END
  END q[195]
  PIN q[196]
    DIRECTION OUTPUT ;
    USE SIGNAL ;
    PORT
      LAYER M4 ;
        RECT  25.836 13.392 25.92 13.416 ;
    END
  END q[196]
  PIN q[197]
    DIRECTION OUTPUT ;
    USE SIGNAL ;
    PORT
      LAYER M4 ;
        RECT  25.836 13.488 25.92 13.512 ;
    END
  END q[197]
  PIN q[198]
    DIRECTION OUTPUT ;
    USE SIGNAL ;
    PORT
      LAYER M4 ;
        RECT  25.836 13.584 25.92 13.608 ;
    END
  END q[198]
  PIN q[199]
    DIRECTION OUTPUT ;
    USE SIGNAL ;
    PORT
      LAYER M4 ;
        RECT  25.836 13.68 25.92 13.704 ;
    END
  END q[199]
  PIN q[19]
    DIRECTION OUTPUT ;
    USE SIGNAL ;
    PORT
      LAYER M4 ;
        RECT  25.836 27.888 25.92 27.912 ;
    END
  END q[19]
  PIN q[1]
    DIRECTION OUTPUT ;
    USE SIGNAL ;
    PORT
      LAYER M4 ;
        RECT  25.836 26.16 25.92 26.184 ;
    END
  END q[1]
  PIN q[200]
    DIRECTION OUTPUT ;
    USE SIGNAL ;
    PORT
      LAYER M4 ;
        RECT  25.836 13.776 25.92 13.8 ;
    END
  END q[200]
  PIN q[201]
    DIRECTION OUTPUT ;
    USE SIGNAL ;
    PORT
      LAYER M4 ;
        RECT  25.836 13.872 25.92 13.896 ;
    END
  END q[201]
  PIN q[202]
    DIRECTION OUTPUT ;
    USE SIGNAL ;
    PORT
      LAYER M4 ;
        RECT  25.836 13.968 25.92 13.992 ;
    END
  END q[202]
  PIN q[203]
    DIRECTION OUTPUT ;
    USE SIGNAL ;
    PORT
      LAYER M4 ;
        RECT  25.836 14.064 25.92 14.088 ;
    END
  END q[203]
  PIN q[204]
    DIRECTION OUTPUT ;
    USE SIGNAL ;
    PORT
      LAYER M4 ;
        RECT  25.836 14.16 25.92 14.184 ;
    END
  END q[204]
  PIN q[205]
    DIRECTION OUTPUT ;
    USE SIGNAL ;
    PORT
      LAYER M4 ;
        RECT  25.836 14.256 25.92 14.28 ;
    END
  END q[205]
  PIN q[206]
    DIRECTION OUTPUT ;
    USE SIGNAL ;
    PORT
      LAYER M4 ;
        RECT  25.836 14.352 25.92 14.376 ;
    END
  END q[206]
  PIN q[207]
    DIRECTION OUTPUT ;
    USE SIGNAL ;
    PORT
      LAYER M4 ;
        RECT  25.836 14.448 25.92 14.472 ;
    END
  END q[207]
  PIN q[208]
    DIRECTION OUTPUT ;
    USE SIGNAL ;
    PORT
      LAYER M4 ;
        RECT  25.836 14.544 25.92 14.568 ;
    END
  END q[208]
  PIN q[209]
    DIRECTION OUTPUT ;
    USE SIGNAL ;
    PORT
      LAYER M4 ;
        RECT  25.836 14.64 25.92 14.664 ;
    END
  END q[209]
  PIN q[20]
    DIRECTION OUTPUT ;
    USE SIGNAL ;
    PORT
      LAYER M4 ;
        RECT  25.836 27.984 25.92 28.008 ;
    END
  END q[20]
  PIN q[210]
    DIRECTION OUTPUT ;
    USE SIGNAL ;
    PORT
      LAYER M4 ;
        RECT  25.836 14.736 25.92 14.76 ;
    END
  END q[210]
  PIN q[211]
    DIRECTION OUTPUT ;
    USE SIGNAL ;
    PORT
      LAYER M4 ;
        RECT  25.836 14.832 25.92 14.856 ;
    END
  END q[211]
  PIN q[212]
    DIRECTION OUTPUT ;
    USE SIGNAL ;
    PORT
      LAYER M4 ;
        RECT  25.836 14.928 25.92 14.952 ;
    END
  END q[212]
  PIN q[213]
    DIRECTION OUTPUT ;
    USE SIGNAL ;
    PORT
      LAYER M4 ;
        RECT  25.836 15.024 25.92 15.048 ;
    END
  END q[213]
  PIN q[214]
    DIRECTION OUTPUT ;
    USE SIGNAL ;
    PORT
      LAYER M4 ;
        RECT  25.836 15.12 25.92 15.144 ;
    END
  END q[214]
  PIN q[215]
    DIRECTION OUTPUT ;
    USE SIGNAL ;
    PORT
      LAYER M4 ;
        RECT  25.836 15.216 25.92 15.24 ;
    END
  END q[215]
  PIN q[216]
    DIRECTION OUTPUT ;
    USE SIGNAL ;
    PORT
      LAYER M4 ;
        RECT  25.836 15.312 25.92 15.336 ;
    END
  END q[216]
  PIN q[217]
    DIRECTION OUTPUT ;
    USE SIGNAL ;
    PORT
      LAYER M4 ;
        RECT  25.836 15.408 25.92 15.432 ;
    END
  END q[217]
  PIN q[218]
    DIRECTION OUTPUT ;
    USE SIGNAL ;
    PORT
      LAYER M4 ;
        RECT  25.836 15.504 25.92 15.528 ;
    END
  END q[218]
  PIN q[219]
    DIRECTION OUTPUT ;
    USE SIGNAL ;
    PORT
      LAYER M4 ;
        RECT  25.836 15.6 25.92 15.624 ;
    END
  END q[219]
  PIN q[21]
    DIRECTION OUTPUT ;
    USE SIGNAL ;
    PORT
      LAYER M4 ;
        RECT  25.836 28.08 25.92 28.104 ;
    END
  END q[21]
  PIN q[220]
    DIRECTION OUTPUT ;
    USE SIGNAL ;
    PORT
      LAYER M4 ;
        RECT  25.836 15.696 25.92 15.72 ;
    END
  END q[220]
  PIN q[221]
    DIRECTION OUTPUT ;
    USE SIGNAL ;
    PORT
      LAYER M4 ;
        RECT  25.836 15.792 25.92 15.816 ;
    END
  END q[221]
  PIN q[222]
    DIRECTION OUTPUT ;
    USE SIGNAL ;
    PORT
      LAYER M4 ;
        RECT  25.836 15.888 25.92 15.912 ;
    END
  END q[222]
  PIN q[223]
    DIRECTION OUTPUT ;
    USE SIGNAL ;
    PORT
      LAYER M4 ;
        RECT  25.836 15.984 25.92 16.008 ;
    END
  END q[223]
  PIN q[224]
    DIRECTION OUTPUT ;
    USE SIGNAL ;
    PORT
      LAYER M4 ;
        RECT  25.836 16.08 25.92 16.104 ;
    END
  END q[224]
  PIN q[225]
    DIRECTION OUTPUT ;
    USE SIGNAL ;
    PORT
      LAYER M4 ;
        RECT  25.836 16.176 25.92 16.2 ;
    END
  END q[225]
  PIN q[226]
    DIRECTION OUTPUT ;
    USE SIGNAL ;
    PORT
      LAYER M4 ;
        RECT  25.836 16.272 25.92 16.296 ;
    END
  END q[226]
  PIN q[227]
    DIRECTION OUTPUT ;
    USE SIGNAL ;
    PORT
      LAYER M4 ;
        RECT  25.836 16.368 25.92 16.392 ;
    END
  END q[227]
  PIN q[228]
    DIRECTION OUTPUT ;
    USE SIGNAL ;
    PORT
      LAYER M4 ;
        RECT  25.836 16.464 25.92 16.488 ;
    END
  END q[228]
  PIN q[229]
    DIRECTION OUTPUT ;
    USE SIGNAL ;
    PORT
      LAYER M4 ;
        RECT  25.836 16.56 25.92 16.584 ;
    END
  END q[229]
  PIN q[22]
    DIRECTION OUTPUT ;
    USE SIGNAL ;
    PORT
      LAYER M4 ;
        RECT  25.836 28.176 25.92 28.2 ;
    END
  END q[22]
  PIN q[230]
    DIRECTION OUTPUT ;
    USE SIGNAL ;
    PORT
      LAYER M4 ;
        RECT  25.836 16.656 25.92 16.68 ;
    END
  END q[230]
  PIN q[231]
    DIRECTION OUTPUT ;
    USE SIGNAL ;
    PORT
      LAYER M4 ;
        RECT  25.836 16.752 25.92 16.776 ;
    END
  END q[231]
  PIN q[232]
    DIRECTION OUTPUT ;
    USE SIGNAL ;
    PORT
      LAYER M4 ;
        RECT  25.836 16.848 25.92 16.872 ;
    END
  END q[232]
  PIN q[233]
    DIRECTION OUTPUT ;
    USE SIGNAL ;
    PORT
      LAYER M4 ;
        RECT  25.836 16.944 25.92 16.968 ;
    END
  END q[233]
  PIN q[234]
    DIRECTION OUTPUT ;
    USE SIGNAL ;
    PORT
      LAYER M4 ;
        RECT  25.836 17.04 25.92 17.064 ;
    END
  END q[234]
  PIN q[235]
    DIRECTION OUTPUT ;
    USE SIGNAL ;
    PORT
      LAYER M4 ;
        RECT  25.836 17.136 25.92 17.16 ;
    END
  END q[235]
  PIN q[236]
    DIRECTION OUTPUT ;
    USE SIGNAL ;
    PORT
      LAYER M4 ;
        RECT  25.836 17.232 25.92 17.256 ;
    END
  END q[236]
  PIN q[237]
    DIRECTION OUTPUT ;
    USE SIGNAL ;
    PORT
      LAYER M4 ;
        RECT  25.836 17.328 25.92 17.352 ;
    END
  END q[237]
  PIN q[238]
    DIRECTION OUTPUT ;
    USE SIGNAL ;
    PORT
      LAYER M4 ;
        RECT  25.836 17.424 25.92 17.448 ;
    END
  END q[238]
  PIN q[239]
    DIRECTION OUTPUT ;
    USE SIGNAL ;
    PORT
      LAYER M4 ;
        RECT  25.836 17.52 25.92 17.544 ;
    END
  END q[239]
  PIN q[23]
    DIRECTION OUTPUT ;
    USE SIGNAL ;
    PORT
      LAYER M4 ;
        RECT  25.836 28.272 25.92 28.296 ;
    END
  END q[23]
  PIN q[240]
    DIRECTION OUTPUT ;
    USE SIGNAL ;
    PORT
      LAYER M4 ;
        RECT  25.836 17.616 25.92 17.64 ;
    END
  END q[240]
  PIN q[241]
    DIRECTION OUTPUT ;
    USE SIGNAL ;
    PORT
      LAYER M4 ;
        RECT  25.836 17.712 25.92 17.736 ;
    END
  END q[241]
  PIN q[242]
    DIRECTION OUTPUT ;
    USE SIGNAL ;
    PORT
      LAYER M4 ;
        RECT  25.836 17.808 25.92 17.832 ;
    END
  END q[242]
  PIN q[243]
    DIRECTION OUTPUT ;
    USE SIGNAL ;
    PORT
      LAYER M4 ;
        RECT  25.836 17.904 25.92 17.928 ;
    END
  END q[243]
  PIN q[244]
    DIRECTION OUTPUT ;
    USE SIGNAL ;
    PORT
      LAYER M4 ;
        RECT  25.836 18 25.92 18.024 ;
    END
  END q[244]
  PIN q[245]
    DIRECTION OUTPUT ;
    USE SIGNAL ;
    PORT
      LAYER M4 ;
        RECT  25.836 18.096 25.92 18.12 ;
    END
  END q[245]
  PIN q[246]
    DIRECTION OUTPUT ;
    USE SIGNAL ;
    PORT
      LAYER M4 ;
        RECT  25.836 18.192 25.92 18.216 ;
    END
  END q[246]
  PIN q[247]
    DIRECTION OUTPUT ;
    USE SIGNAL ;
    PORT
      LAYER M4 ;
        RECT  25.836 18.288 25.92 18.312 ;
    END
  END q[247]
  PIN q[248]
    DIRECTION OUTPUT ;
    USE SIGNAL ;
    PORT
      LAYER M4 ;
        RECT  25.836 18.384 25.92 18.408 ;
    END
  END q[248]
  PIN q[249]
    DIRECTION OUTPUT ;
    USE SIGNAL ;
    PORT
      LAYER M4 ;
        RECT  25.836 18.48 25.92 18.504 ;
    END
  END q[249]
  PIN q[24]
    DIRECTION OUTPUT ;
    USE SIGNAL ;
    PORT
      LAYER M4 ;
        RECT  25.836 28.368 25.92 28.392 ;
    END
  END q[24]
  PIN q[250]
    DIRECTION OUTPUT ;
    USE SIGNAL ;
    PORT
      LAYER M4 ;
        RECT  25.836 18.576 25.92 18.6 ;
    END
  END q[250]
  PIN q[251]
    DIRECTION OUTPUT ;
    USE SIGNAL ;
    PORT
      LAYER M4 ;
        RECT  25.836 18.672 25.92 18.696 ;
    END
  END q[251]
  PIN q[252]
    DIRECTION OUTPUT ;
    USE SIGNAL ;
    PORT
      LAYER M4 ;
        RECT  25.836 18.768 25.92 18.792 ;
    END
  END q[252]
  PIN q[253]
    DIRECTION OUTPUT ;
    USE SIGNAL ;
    PORT
      LAYER M4 ;
        RECT  25.836 18.864 25.92 18.888 ;
    END
  END q[253]
  PIN q[254]
    DIRECTION OUTPUT ;
    USE SIGNAL ;
    PORT
      LAYER M4 ;
        RECT  25.836 18.96 25.92 18.984 ;
    END
  END q[254]
  PIN q[255]
    DIRECTION OUTPUT ;
    USE SIGNAL ;
    PORT
      LAYER M4 ;
        RECT  25.836 19.056 25.92 19.08 ;
    END
  END q[255]
  PIN q[25]
    DIRECTION OUTPUT ;
    USE SIGNAL ;
    PORT
      LAYER M4 ;
        RECT  25.836 28.464 25.92 28.488 ;
    END
  END q[25]
  PIN q[26]
    DIRECTION OUTPUT ;
    USE SIGNAL ;
    PORT
      LAYER M4 ;
        RECT  25.836 28.56 25.92 28.584 ;
    END
  END q[26]
  PIN q[27]
    DIRECTION OUTPUT ;
    USE SIGNAL ;
    PORT
      LAYER M4 ;
        RECT  25.836 28.656 25.92 28.68 ;
    END
  END q[27]
  PIN q[28]
    DIRECTION OUTPUT ;
    USE SIGNAL ;
    PORT
      LAYER M4 ;
        RECT  25.836 28.752 25.92 28.776 ;
    END
  END q[28]
  PIN q[29]
    DIRECTION OUTPUT ;
    USE SIGNAL ;
    PORT
      LAYER M4 ;
        RECT  25.836 28.848 25.92 28.872 ;
    END
  END q[29]
  PIN q[2]
    DIRECTION OUTPUT ;
    USE SIGNAL ;
    PORT
      LAYER M4 ;
        RECT  25.836 26.256 25.92 26.28 ;
    END
  END q[2]
  PIN q[30]
    DIRECTION OUTPUT ;
    USE SIGNAL ;
    PORT
      LAYER M4 ;
        RECT  25.836 28.944 25.92 28.968 ;
    END
  END q[30]
  PIN q[31]
    DIRECTION OUTPUT ;
    USE SIGNAL ;
    PORT
      LAYER M4 ;
        RECT  25.836 29.04 25.92 29.064 ;
    END
  END q[31]
  PIN q[32]
    DIRECTION OUTPUT ;
    USE SIGNAL ;
    PORT
      LAYER M4 ;
        RECT  25.836 29.136 25.92 29.16 ;
    END
  END q[32]
  PIN q[33]
    DIRECTION OUTPUT ;
    USE SIGNAL ;
    PORT
      LAYER M4 ;
        RECT  25.836 29.232 25.92 29.256 ;
    END
  END q[33]
  PIN q[34]
    DIRECTION OUTPUT ;
    USE SIGNAL ;
    PORT
      LAYER M4 ;
        RECT  25.836 29.328 25.92 29.352 ;
    END
  END q[34]
  PIN q[35]
    DIRECTION OUTPUT ;
    USE SIGNAL ;
    PORT
      LAYER M4 ;
        RECT  25.836 29.424 25.92 29.448 ;
    END
  END q[35]
  PIN q[36]
    DIRECTION OUTPUT ;
    USE SIGNAL ;
    PORT
      LAYER M4 ;
        RECT  25.836 29.52 25.92 29.544 ;
    END
  END q[36]
  PIN q[37]
    DIRECTION OUTPUT ;
    USE SIGNAL ;
    PORT
      LAYER M4 ;
        RECT  25.836 29.616 25.92 29.64 ;
    END
  END q[37]
  PIN q[38]
    DIRECTION OUTPUT ;
    USE SIGNAL ;
    PORT
      LAYER M4 ;
        RECT  25.836 29.712 25.92 29.736 ;
    END
  END q[38]
  PIN q[39]
    DIRECTION OUTPUT ;
    USE SIGNAL ;
    PORT
      LAYER M4 ;
        RECT  25.836 29.808 25.92 29.832 ;
    END
  END q[39]
  PIN q[3]
    DIRECTION OUTPUT ;
    USE SIGNAL ;
    PORT
      LAYER M4 ;
        RECT  25.836 26.352 25.92 26.376 ;
    END
  END q[3]
  PIN q[40]
    DIRECTION OUTPUT ;
    USE SIGNAL ;
    PORT
      LAYER M4 ;
        RECT  25.836 29.904 25.92 29.928 ;
    END
  END q[40]
  PIN q[41]
    DIRECTION OUTPUT ;
    USE SIGNAL ;
    PORT
      LAYER M4 ;
        RECT  25.836 30 25.92 30.024 ;
    END
  END q[41]
  PIN q[42]
    DIRECTION OUTPUT ;
    USE SIGNAL ;
    PORT
      LAYER M4 ;
        RECT  25.836 30.096 25.92 30.12 ;
    END
  END q[42]
  PIN q[43]
    DIRECTION OUTPUT ;
    USE SIGNAL ;
    PORT
      LAYER M4 ;
        RECT  25.836 30.192 25.92 30.216 ;
    END
  END q[43]
  PIN q[44]
    DIRECTION OUTPUT ;
    USE SIGNAL ;
    PORT
      LAYER M4 ;
        RECT  25.836 30.288 25.92 30.312 ;
    END
  END q[44]
  PIN q[45]
    DIRECTION OUTPUT ;
    USE SIGNAL ;
    PORT
      LAYER M4 ;
        RECT  25.836 30.384 25.92 30.408 ;
    END
  END q[45]
  PIN q[46]
    DIRECTION OUTPUT ;
    USE SIGNAL ;
    PORT
      LAYER M4 ;
        RECT  25.836 30.48 25.92 30.504 ;
    END
  END q[46]
  PIN q[47]
    DIRECTION OUTPUT ;
    USE SIGNAL ;
    PORT
      LAYER M4 ;
        RECT  25.836 30.576 25.92 30.6 ;
    END
  END q[47]
  PIN q[48]
    DIRECTION OUTPUT ;
    USE SIGNAL ;
    PORT
      LAYER M4 ;
        RECT  25.836 30.672 25.92 30.696 ;
    END
  END q[48]
  PIN q[49]
    DIRECTION OUTPUT ;
    USE SIGNAL ;
    PORT
      LAYER M4 ;
        RECT  25.836 30.768 25.92 30.792 ;
    END
  END q[49]
  PIN q[4]
    DIRECTION OUTPUT ;
    USE SIGNAL ;
    PORT
      LAYER M4 ;
        RECT  25.836 26.448 25.92 26.472 ;
    END
  END q[4]
  PIN q[50]
    DIRECTION OUTPUT ;
    USE SIGNAL ;
    PORT
      LAYER M4 ;
        RECT  25.836 30.864 25.92 30.888 ;
    END
  END q[50]
  PIN q[51]
    DIRECTION OUTPUT ;
    USE SIGNAL ;
    PORT
      LAYER M4 ;
        RECT  25.836 30.96 25.92 30.984 ;
    END
  END q[51]
  PIN q[52]
    DIRECTION OUTPUT ;
    USE SIGNAL ;
    PORT
      LAYER M4 ;
        RECT  25.836 31.056 25.92 31.08 ;
    END
  END q[52]
  PIN q[53]
    DIRECTION OUTPUT ;
    USE SIGNAL ;
    PORT
      LAYER M4 ;
        RECT  25.836 31.152 25.92 31.176 ;
    END
  END q[53]
  PIN q[54]
    DIRECTION OUTPUT ;
    USE SIGNAL ;
    PORT
      LAYER M4 ;
        RECT  25.836 31.248 25.92 31.272 ;
    END
  END q[54]
  PIN q[55]
    DIRECTION OUTPUT ;
    USE SIGNAL ;
    PORT
      LAYER M4 ;
        RECT  25.836 31.344 25.92 31.368 ;
    END
  END q[55]
  PIN q[56]
    DIRECTION OUTPUT ;
    USE SIGNAL ;
    PORT
      LAYER M4 ;
        RECT  25.836 31.44 25.92 31.464 ;
    END
  END q[56]
  PIN q[57]
    DIRECTION OUTPUT ;
    USE SIGNAL ;
    PORT
      LAYER M4 ;
        RECT  25.836 31.536 25.92 31.56 ;
    END
  END q[57]
  PIN q[58]
    DIRECTION OUTPUT ;
    USE SIGNAL ;
    PORT
      LAYER M4 ;
        RECT  25.836 31.632 25.92 31.656 ;
    END
  END q[58]
  PIN q[59]
    DIRECTION OUTPUT ;
    USE SIGNAL ;
    PORT
      LAYER M4 ;
        RECT  25.836 31.728 25.92 31.752 ;
    END
  END q[59]
  PIN q[5]
    DIRECTION OUTPUT ;
    USE SIGNAL ;
    PORT
      LAYER M4 ;
        RECT  25.836 26.544 25.92 26.568 ;
    END
  END q[5]
  PIN q[60]
    DIRECTION OUTPUT ;
    USE SIGNAL ;
    PORT
      LAYER M4 ;
        RECT  25.836 31.824 25.92 31.848 ;
    END
  END q[60]
  PIN q[61]
    DIRECTION OUTPUT ;
    USE SIGNAL ;
    PORT
      LAYER M4 ;
        RECT  25.836 31.92 25.92 31.944 ;
    END
  END q[61]
  PIN q[62]
    DIRECTION OUTPUT ;
    USE SIGNAL ;
    PORT
      LAYER M4 ;
        RECT  25.836 32.016 25.92 32.04 ;
    END
  END q[62]
  PIN q[63]
    DIRECTION OUTPUT ;
    USE SIGNAL ;
    PORT
      LAYER M4 ;
        RECT  25.836 32.112 25.92 32.136 ;
    END
  END q[63]
  PIN q[64]
    DIRECTION OUTPUT ;
    USE SIGNAL ;
    PORT
      LAYER M4 ;
        RECT  25.836 35.28 25.92 35.304 ;
    END
  END q[64]
  PIN q[65]
    DIRECTION OUTPUT ;
    USE SIGNAL ;
    PORT
      LAYER M4 ;
        RECT  25.836 35.376 25.92 35.4 ;
    END
  END q[65]
  PIN q[66]
    DIRECTION OUTPUT ;
    USE SIGNAL ;
    PORT
      LAYER M4 ;
        RECT  25.836 35.472 25.92 35.496 ;
    END
  END q[66]
  PIN q[67]
    DIRECTION OUTPUT ;
    USE SIGNAL ;
    PORT
      LAYER M4 ;
        RECT  25.836 35.568 25.92 35.592 ;
    END
  END q[67]
  PIN q[68]
    DIRECTION OUTPUT ;
    USE SIGNAL ;
    PORT
      LAYER M4 ;
        RECT  25.836 35.664 25.92 35.688 ;
    END
  END q[68]
  PIN q[69]
    DIRECTION OUTPUT ;
    USE SIGNAL ;
    PORT
      LAYER M4 ;
        RECT  25.836 35.76 25.92 35.784 ;
    END
  END q[69]
  PIN q[6]
    DIRECTION OUTPUT ;
    USE SIGNAL ;
    PORT
      LAYER M4 ;
        RECT  25.836 26.64 25.92 26.664 ;
    END
  END q[6]
  PIN q[70]
    DIRECTION OUTPUT ;
    USE SIGNAL ;
    PORT
      LAYER M4 ;
        RECT  25.836 35.856 25.92 35.88 ;
    END
  END q[70]
  PIN q[71]
    DIRECTION OUTPUT ;
    USE SIGNAL ;
    PORT
      LAYER M4 ;
        RECT  25.836 35.952 25.92 35.976 ;
    END
  END q[71]
  PIN q[72]
    DIRECTION OUTPUT ;
    USE SIGNAL ;
    PORT
      LAYER M4 ;
        RECT  25.836 36.048 25.92 36.072 ;
    END
  END q[72]
  PIN q[73]
    DIRECTION OUTPUT ;
    USE SIGNAL ;
    PORT
      LAYER M4 ;
        RECT  25.836 36.144 25.92 36.168 ;
    END
  END q[73]
  PIN q[74]
    DIRECTION OUTPUT ;
    USE SIGNAL ;
    PORT
      LAYER M4 ;
        RECT  25.836 36.24 25.92 36.264 ;
    END
  END q[74]
  PIN q[75]
    DIRECTION OUTPUT ;
    USE SIGNAL ;
    PORT
      LAYER M4 ;
        RECT  25.836 36.336 25.92 36.36 ;
    END
  END q[75]
  PIN q[76]
    DIRECTION OUTPUT ;
    USE SIGNAL ;
    PORT
      LAYER M4 ;
        RECT  25.836 36.432 25.92 36.456 ;
    END
  END q[76]
  PIN q[77]
    DIRECTION OUTPUT ;
    USE SIGNAL ;
    PORT
      LAYER M4 ;
        RECT  25.836 36.528 25.92 36.552 ;
    END
  END q[77]
  PIN q[78]
    DIRECTION OUTPUT ;
    USE SIGNAL ;
    PORT
      LAYER M4 ;
        RECT  25.836 36.624 25.92 36.648 ;
    END
  END q[78]
  PIN q[79]
    DIRECTION OUTPUT ;
    USE SIGNAL ;
    PORT
      LAYER M4 ;
        RECT  25.836 36.72 25.92 36.744 ;
    END
  END q[79]
  PIN q[7]
    DIRECTION OUTPUT ;
    USE SIGNAL ;
    PORT
      LAYER M4 ;
        RECT  25.836 26.736 25.92 26.76 ;
    END
  END q[7]
  PIN q[80]
    DIRECTION OUTPUT ;
    USE SIGNAL ;
    PORT
      LAYER M4 ;
        RECT  25.836 36.816 25.92 36.84 ;
    END
  END q[80]
  PIN q[81]
    DIRECTION OUTPUT ;
    USE SIGNAL ;
    PORT
      LAYER M4 ;
        RECT  25.836 36.912 25.92 36.936 ;
    END
  END q[81]
  PIN q[82]
    DIRECTION OUTPUT ;
    USE SIGNAL ;
    PORT
      LAYER M4 ;
        RECT  25.836 37.008 25.92 37.032 ;
    END
  END q[82]
  PIN q[83]
    DIRECTION OUTPUT ;
    USE SIGNAL ;
    PORT
      LAYER M4 ;
        RECT  25.836 37.104 25.92 37.128 ;
    END
  END q[83]
  PIN q[84]
    DIRECTION OUTPUT ;
    USE SIGNAL ;
    PORT
      LAYER M4 ;
        RECT  25.836 37.2 25.92 37.224 ;
    END
  END q[84]
  PIN q[85]
    DIRECTION OUTPUT ;
    USE SIGNAL ;
    PORT
      LAYER M4 ;
        RECT  25.836 37.296 25.92 37.32 ;
    END
  END q[85]
  PIN q[86]
    DIRECTION OUTPUT ;
    USE SIGNAL ;
    PORT
      LAYER M4 ;
        RECT  25.836 37.392 25.92 37.416 ;
    END
  END q[86]
  PIN q[87]
    DIRECTION OUTPUT ;
    USE SIGNAL ;
    PORT
      LAYER M4 ;
        RECT  25.836 37.488 25.92 37.512 ;
    END
  END q[87]
  PIN q[88]
    DIRECTION OUTPUT ;
    USE SIGNAL ;
    PORT
      LAYER M4 ;
        RECT  25.836 37.584 25.92 37.608 ;
    END
  END q[88]
  PIN q[89]
    DIRECTION OUTPUT ;
    USE SIGNAL ;
    PORT
      LAYER M4 ;
        RECT  25.836 37.68 25.92 37.704 ;
    END
  END q[89]
  PIN q[8]
    DIRECTION OUTPUT ;
    USE SIGNAL ;
    PORT
      LAYER M4 ;
        RECT  25.836 26.832 25.92 26.856 ;
    END
  END q[8]
  PIN q[90]
    DIRECTION OUTPUT ;
    USE SIGNAL ;
    PORT
      LAYER M4 ;
        RECT  25.836 37.776 25.92 37.8 ;
    END
  END q[90]
  PIN q[91]
    DIRECTION OUTPUT ;
    USE SIGNAL ;
    PORT
      LAYER M4 ;
        RECT  25.836 37.872 25.92 37.896 ;
    END
  END q[91]
  PIN q[92]
    DIRECTION OUTPUT ;
    USE SIGNAL ;
    PORT
      LAYER M4 ;
        RECT  25.836 37.968 25.92 37.992 ;
    END
  END q[92]
  PIN q[93]
    DIRECTION OUTPUT ;
    USE SIGNAL ;
    PORT
      LAYER M4 ;
        RECT  25.836 38.064 25.92 38.088 ;
    END
  END q[93]
  PIN q[94]
    DIRECTION OUTPUT ;
    USE SIGNAL ;
    PORT
      LAYER M4 ;
        RECT  25.836 38.16 25.92 38.184 ;
    END
  END q[94]
  PIN q[95]
    DIRECTION OUTPUT ;
    USE SIGNAL ;
    PORT
      LAYER M4 ;
        RECT  25.836 38.256 25.92 38.28 ;
    END
  END q[95]
  PIN q[96]
    DIRECTION OUTPUT ;
    USE SIGNAL ;
    PORT
      LAYER M4 ;
        RECT  25.836 32.208 25.92 32.232 ;
    END
  END q[96]
  PIN q[97]
    DIRECTION OUTPUT ;
    USE SIGNAL ;
    PORT
      LAYER M4 ;
        RECT  25.836 32.304 25.92 32.328 ;
    END
  END q[97]
  PIN q[98]
    DIRECTION OUTPUT ;
    USE SIGNAL ;
    PORT
      LAYER M4 ;
        RECT  25.836 32.4 25.92 32.424 ;
    END
  END q[98]
  PIN q[99]
    DIRECTION OUTPUT ;
    USE SIGNAL ;
    PORT
      LAYER M4 ;
        RECT  25.836 32.496 25.92 32.52 ;
    END
  END q[99]
  PIN q[9]
    DIRECTION OUTPUT ;
    USE SIGNAL ;
    PORT
      LAYER M4 ;
        RECT  25.836 26.928 25.92 26.952 ;
    END
  END q[9]
  PIN VDD
    DIRECTION INOUT ;
    USE POWER ;
    PORT
      LAYER M5 ;
        RECT  21.492 2.151 21.612 49.689 ;
        RECT  18.792 2.151 18.912 49.689 ;
        RECT  16.092 2.151 16.212 49.689 ;
        RECT  13.392 2.151 13.512 49.689 ;
        RECT  10.692 2.151 10.812 49.689 ;
        RECT  7.992 2.151 8.112 49.689 ;
        RECT  5.292 2.151 5.412 49.689 ;
        RECT  2.592 2.151 2.712 49.689 ;
    END
  END VDD
  PIN VSS
    DIRECTION INOUT ;
    USE GROUND ;
    PORT
      LAYER M5 ;
        RECT  21.3 2.137 21.42 49.703 ;
        RECT  18.6 2.137 18.72 49.703 ;
        RECT  15.9 2.137 16.02 49.703 ;
        RECT  13.2 2.137 13.32 49.703 ;
        RECT  10.5 2.137 10.62 49.703 ;
        RECT  7.8 2.137 7.92 49.703 ;
        RECT  5.1 2.137 5.22 49.703 ;
        RECT  2.4 2.137 2.52 49.703 ;
    END
  END VSS
  # OT_OBS_CLOSED layer=M5 d_um=1.536 added=24
  OBS
    LAYER RVTN ;
     RECT  2.16 2.16 23.76 2.295 ;
     RECT  2.16 2.565 23.76 2.835 ;
     RECT  2.16 3.105 23.76 3.375 ;
     RECT  2.16 3.645 23.76 3.915 ;
     RECT  2.16 4.185 23.76 4.455 ;
     RECT  2.16 4.725 23.76 4.995 ;
     RECT  2.16 5.265 23.76 5.535 ;
     RECT  2.16 5.805 23.76 6.075 ;
     RECT  2.16 6.345 23.76 6.615 ;
     RECT  2.16 6.885 23.76 7.155 ;
     RECT  2.16 7.425 23.76 7.695 ;
     RECT  2.16 7.965 23.76 8.235 ;
     RECT  2.16 8.505 23.76 8.775 ;
     RECT  2.16 9.045 23.76 9.315 ;
     RECT  2.16 9.585 23.76 9.855 ;
     RECT  2.16 10.125 23.76 10.395 ;
     RECT  2.16 10.665 23.76 10.935 ;
     RECT  2.16 11.205 23.76 11.475 ;
     RECT  2.16 11.745 23.76 12.015 ;
     RECT  2.16 12.285 23.76 12.555 ;
     RECT  2.16 12.825 23.76 13.095 ;
     RECT  2.16 13.365 23.76 13.635 ;
     RECT  2.16 13.905 23.76 14.175 ;
     RECT  2.16 14.445 23.76 14.715 ;
     RECT  2.16 14.985 23.76 15.255 ;
     RECT  2.16 15.525 23.76 15.795 ;
     RECT  2.16 16.065 23.76 16.335 ;
     RECT  2.16 16.605 23.76 16.875 ;
     RECT  2.16 17.145 23.76 17.415 ;
     RECT  2.16 17.685 23.76 17.955 ;
     RECT  2.16 18.225 23.76 18.495 ;
     RECT  2.16 18.765 23.76 19.035 ;
     RECT  2.16 19.305 23.76 19.575 ;
     RECT  2.16 19.845 23.76 20.115 ;
     RECT  2.16 20.385 23.76 20.655 ;
     RECT  2.16 20.925 23.76 21.195 ;
     RECT  2.16 21.465 23.76 21.735 ;
     RECT  2.16 22.005 23.76 22.275 ;
     RECT  2.16 22.545 23.76 22.815 ;
     RECT  2.16 23.085 23.76 23.355 ;
     RECT  2.16 23.625 23.76 23.895 ;
     RECT  2.16 24.165 23.76 24.435 ;
     RECT  2.16 24.705 23.76 24.975 ;
     RECT  2.16 25.245 23.76 25.515 ;
     RECT  2.16 25.785 23.76 26.055 ;
     RECT  2.16 26.325 23.76 26.595 ;
     RECT  2.16 26.865 23.76 27.135 ;
     RECT  2.16 27.405 23.76 27.675 ;
     RECT  2.16 27.945 23.76 28.215 ;
     RECT  2.16 28.485 23.76 28.755 ;
     RECT  2.16 29.025 23.76 29.295 ;
     RECT  2.16 29.565 23.76 29.835 ;
     RECT  2.16 30.105 23.76 30.375 ;
     RECT  2.16 30.645 23.76 30.915 ;
     RECT  2.16 31.185 23.76 31.455 ;
     RECT  2.16 31.725 23.76 31.995 ;
     RECT  2.16 32.265 23.76 32.535 ;
     RECT  2.16 32.805 23.76 33.075 ;
     RECT  2.16 33.345 23.76 33.615 ;
     RECT  2.16 33.885 23.76 34.155 ;
     RECT  2.16 34.425 23.76 34.695 ;
     RECT  2.16 34.965 23.76 35.235 ;
     RECT  2.16 35.505 23.76 35.775 ;
     RECT  2.16 36.045 23.76 36.315 ;
     RECT  2.16 36.585 23.76 36.855 ;
     RECT  2.16 37.125 23.76 37.395 ;
     RECT  2.16 37.665 23.76 37.935 ;
     RECT  2.16 38.205 23.76 38.475 ;
     RECT  2.16 38.745 23.76 39.015 ;
     RECT  2.16 39.285 23.76 39.555 ;
     RECT  2.16 39.825 23.76 40.095 ;
     RECT  2.16 40.365 23.76 40.635 ;
     RECT  2.16 40.905 23.76 41.175 ;
     RECT  2.16 41.445 23.76 41.715 ;
     RECT  2.16 41.985 23.76 42.255 ;
     RECT  2.16 42.525 23.76 42.795 ;
     RECT  2.16 43.065 23.76 43.335 ;
     RECT  2.16 43.605 23.76 43.875 ;
     RECT  2.16 44.145 23.76 44.415 ;
     RECT  2.16 44.685 23.76 44.955 ;
     RECT  2.16 45.225 23.76 45.495 ;
     RECT  2.16 45.765 23.76 46.035 ;
     RECT  2.16 46.305 23.76 46.575 ;
     RECT  2.16 46.845 23.76 47.115 ;
     RECT  2.16 47.385 23.76 47.655 ;
     RECT  2.16 47.925 23.76 48.195 ;
     RECT  2.16 48.465 23.76 48.735 ;
     RECT  2.16 49.005 23.76 49.275 ;
     RECT  2.16 49.545 23.76 49.68 ;
    LAYER RVTP ;
     RECT  2.16 2.295 23.76 2.565 ;
     RECT  2.16 2.835 23.76 3.105 ;
     RECT  2.16 3.375 23.76 3.645 ;
     RECT  2.16 3.915 23.76 4.185 ;
     RECT  2.16 4.455 23.76 4.725 ;
     RECT  2.16 4.995 23.76 5.265 ;
     RECT  2.16 5.535 23.76 5.805 ;
     RECT  2.16 6.075 23.76 6.345 ;
     RECT  2.16 6.615 23.76 6.885 ;
     RECT  2.16 7.155 23.76 7.425 ;
     RECT  2.16 7.695 23.76 7.965 ;
     RECT  2.16 8.235 23.76 8.505 ;
     RECT  2.16 8.775 23.76 9.045 ;
     RECT  2.16 9.315 23.76 9.585 ;
     RECT  2.16 9.855 23.76 10.125 ;
     RECT  2.16 10.395 23.76 10.665 ;
     RECT  2.16 10.935 23.76 11.205 ;
     RECT  2.16 11.475 23.76 11.745 ;
     RECT  2.16 12.015 23.76 12.285 ;
     RECT  2.16 12.555 23.76 12.825 ;
     RECT  2.16 13.095 23.76 13.365 ;
     RECT  2.16 13.635 23.76 13.905 ;
     RECT  2.16 14.175 23.76 14.445 ;
     RECT  2.16 14.715 23.76 14.985 ;
     RECT  2.16 15.255 23.76 15.525 ;
     RECT  2.16 15.795 23.76 16.065 ;
     RECT  2.16 16.335 23.76 16.605 ;
     RECT  2.16 16.875 23.76 17.145 ;
     RECT  2.16 17.415 23.76 17.685 ;
     RECT  2.16 17.955 23.76 18.225 ;
     RECT  2.16 18.495 23.76 18.765 ;
     RECT  2.16 19.035 23.76 19.305 ;
     RECT  2.16 19.575 23.76 19.845 ;
     RECT  2.16 20.115 23.76 20.385 ;
     RECT  2.16 20.655 23.76 20.925 ;
     RECT  2.16 21.195 23.76 21.465 ;
     RECT  2.16 21.735 23.76 22.005 ;
     RECT  2.16 22.275 23.76 22.545 ;
     RECT  2.16 22.815 23.76 23.085 ;
     RECT  2.16 23.355 23.76 23.625 ;
     RECT  2.16 23.895 23.76 24.165 ;
     RECT  2.16 24.435 23.76 24.705 ;
     RECT  2.16 24.975 23.76 25.245 ;
     RECT  2.16 25.515 23.76 25.785 ;
     RECT  2.16 26.055 23.76 26.325 ;
     RECT  2.16 26.595 23.76 26.865 ;
     RECT  2.16 27.135 23.76 27.405 ;
     RECT  2.16 27.675 23.76 27.945 ;
     RECT  2.16 28.215 23.76 28.485 ;
     RECT  2.16 28.755 23.76 29.025 ;
     RECT  2.16 29.295 23.76 29.565 ;
     RECT  2.16 29.835 23.76 30.105 ;
     RECT  2.16 30.375 23.76 30.645 ;
     RECT  2.16 30.915 23.76 31.185 ;
     RECT  2.16 31.455 23.76 31.725 ;
     RECT  2.16 31.995 23.76 32.265 ;
     RECT  2.16 32.535 23.76 32.805 ;
     RECT  2.16 33.075 23.76 33.345 ;
     RECT  2.16 33.615 23.76 33.885 ;
     RECT  2.16 34.155 23.76 34.425 ;
     RECT  2.16 34.695 23.76 34.965 ;
     RECT  2.16 35.235 23.76 35.505 ;
     RECT  2.16 35.775 23.76 36.045 ;
     RECT  2.16 36.315 23.76 36.585 ;
     RECT  2.16 36.855 23.76 37.125 ;
     RECT  2.16 37.395 23.76 37.665 ;
     RECT  2.16 37.935 23.76 38.205 ;
     RECT  2.16 38.475 23.76 38.745 ;
     RECT  2.16 39.015 23.76 39.285 ;
     RECT  2.16 39.555 23.76 39.825 ;
     RECT  2.16 40.095 23.76 40.365 ;
     RECT  2.16 40.635 23.76 40.905 ;
     RECT  2.16 41.175 23.76 41.445 ;
     RECT  2.16 41.715 23.76 41.985 ;
     RECT  2.16 42.255 23.76 42.525 ;
     RECT  2.16 42.795 23.76 43.065 ;
     RECT  2.16 43.335 23.76 43.605 ;
     RECT  2.16 43.875 23.76 44.145 ;
     RECT  2.16 44.415 23.76 44.685 ;
     RECT  2.16 44.955 23.76 45.225 ;
     RECT  2.16 45.495 23.76 45.765 ;
     RECT  2.16 46.035 23.76 46.305 ;
     RECT  2.16 46.575 23.76 46.845 ;
     RECT  2.16 47.115 23.76 47.385 ;
     RECT  2.16 47.655 23.76 47.925 ;
     RECT  2.16 48.195 23.76 48.465 ;
     RECT  2.16 48.735 23.76 49.005 ;
     RECT  2.16 49.275 23.76 49.545 ;
    LAYER M1 ;
     RECT  2.16 2.151 23.76 49.689 ;
    LAYER M2 ;
     RECT  0.067 37.602 0.103 37.62 ;
     RECT  0.067 40.104 0.103 40.122 ;
     RECT  0.103 12.87 0.139 12.888 ;
     RECT  0.103 16.38 0.139 16.398 ;
     RECT  0.103 17.622 0.139 18.18 ;
     RECT  0.103 23.832 0.139 23.85 ;
     RECT  0.103 33.354 0.139 33.372 ;
     RECT  0.103 36.936 0.167 37.62 ;
     RECT  0.103 25.101 0.175 25.119 ;
     RECT  0.139 33.354 0.175 33.57 ;
     RECT  0.175 25.056 0.203 25.119 ;
     RECT  0.139 12.87 0.247 13.59 ;
     RECT  0.167 36.936 0.275 36.954 ;
     RECT  0.103 22.752 0.463 22.77 ;
     RECT  0.247 12.87 0.535 13.662 ;
     RECT  0.463 21.816 0.535 21.834 ;
     RECT  0.463 22.752 0.535 22.806 ;
     RECT  0.103 27.342 0.535 27.36 ;
     RECT  0.103 28.8 0.535 28.818 ;
     RECT  0.103 30.186 0.535 30.204 ;
     RECT  0.103 32.04 0.535 32.058 ;
     RECT  0.175 33.354 0.535 33.876 ;
     RECT  0.535 21.816 0.563 22.806 ;
     RECT  0.535 27.216 1.147 27.36 ;
     RECT  0.535 30.078 1.291 30.204 ;
     RECT  0.103 19.89 1.399 19.908 ;
     RECT  0.103 39.492 1.399 40.122 ;
     RECT  0.203 25.056 1.687 25.074 ;
     RECT  0.535 12.528 2.16 13.662 ;
     RECT  0.103 14.652 2.16 15.318 ;
     RECT  0.139 16.38 2.16 18.18 ;
     RECT  1.399 19.89 2.16 20.142 ;
     RECT  0.563 21.816 2.16 22.77 ;
     RECT  0.139 23.67 2.16 23.85 ;
     RECT  1.687 24.75 2.16 25.074 ;
     RECT  1.147 26.838 2.16 27.36 ;
     RECT  0.535 28.422 2.16 28.818 ;
     RECT  1.291 30.078 2.16 30.402 ;
     RECT  0.535 32.04 2.16 33.876 ;
     RECT  1.147 38.142 2.16 38.16 ;
     RECT  1.399 39.492 2.16 40.86 ;
     RECT  2.16 2.151 23.76 49.689 ;
     RECT  23.76 10.944 23.927 11.394 ;
     RECT  23.76 40.104 23.927 40.824 ;
     RECT  23.927 10.944 23.999 10.962 ;
     RECT  23.927 40.536 24.215 40.824 ;
     RECT  24.215 40.536 24.287 40.698 ;
     RECT  23.76 12.726 24.503 38.934 ;
     RECT  24.503 12.726 24.575 37.314 ;
     RECT  24.575 14.526 25.043 37.314 ;
     RECT  24.503 38.106 25.043 38.394 ;
     RECT  24.575 12.726 25.079 13.662 ;
     RECT  25.043 14.526 25.079 15.084 ;
     RECT  25.043 16.002 25.079 16.974 ;
     RECT  25.043 17.766 25.079 37.314 ;
     RECT  25.043 38.106 25.079 38.124 ;
     RECT  25.079 18.576 25.115 19.944 ;
     RECT  25.079 20.736 25.115 22.338 ;
     RECT  25.079 23.256 25.115 24.462 ;
     RECT  25.079 25.686 25.115 32.562 ;
     RECT  25.079 14.616 25.151 14.976 ;
     RECT  25.115 30.42 25.151 30.438 ;
     RECT  25.151 14.958 25.187 14.976 ;
     RECT  25.115 25.686 25.727 28.008 ;
     RECT  25.079 12.906 25.763 13.662 ;
     RECT  25.079 16.38 25.763 16.974 ;
     RECT  25.115 20.862 25.763 22.338 ;
     RECT  25.727 27.99 25.763 28.008 ;
     RECT  25.079 33.318 25.763 35.154 ;
     RECT  25.763 13.374 25.799 13.662 ;
     RECT  25.115 19.278 25.799 19.944 ;
     RECT  25.763 22.212 25.799 22.338 ;
     RECT  25.115 29.106 25.799 29.556 ;
     RECT  25.115 31.626 25.799 32.562 ;
     RECT  25.763 34.236 25.799 35.154 ;
     RECT  25.799 13.374 25.835 13.392 ;
     RECT  25.763 16.416 25.835 16.974 ;
     RECT  25.079 17.766 25.835 17.784 ;
     RECT  25.799 19.278 25.835 19.674 ;
     RECT  25.763 20.862 25.835 21.384 ;
     RECT  25.799 22.32 25.835 22.338 ;
     RECT  25.115 23.256 25.835 23.274 ;
     RECT  25.115 24.444 25.835 24.462 ;
     RECT  25.727 25.686 25.835 26.658 ;
     RECT  25.799 29.106 25.835 29.124 ;
     RECT  25.799 31.626 25.835 32.364 ;
     RECT  25.799 34.398 25.835 35.154 ;
     RECT  25.807 37.908 25.907 37.926 ;
     RECT  24.287 40.536 25.907 40.554 ;
    LAYER M3 ;
     RECT  2.415 2.143 2.505 2.413 ;
     RECT  5.115 2.143 5.205 2.413 ;
     RECT  7.815 2.143 7.905 2.413 ;
     RECT  10.515 2.143 10.605 2.413 ;
     RECT  13.215 2.143 13.305 2.413 ;
     RECT  15.915 2.143 16.005 2.413 ;
     RECT  18.615 2.143 18.705 2.413 ;
     RECT  21.315 2.143 21.405 2.413 ;
     RECT  15.915 2.413 16.197 9.211 ;
     RECT  21.315 2.413 21.597 9.391 ;
     RECT  10.515 2.413 10.797 9.481 ;
     RECT  21.315 9.391 22.23 9.481 ;
     RECT  21.315 9.481 22.626 9.661 ;
     RECT  21.315 9.661 22.662 9.931 ;
     RECT  15.915 9.211 16.614 10.057 ;
     RECT  10.26 9.481 10.797 10.093 ;
     RECT  21.315 9.931 23.418 10.201 ;
     RECT  10.044 10.093 10.797 10.291 ;
     RECT  21.315 10.201 23.526 10.471 ;
     RECT  21.315 10.471 23.67 10.741 ;
     RECT  5.115 2.413 5.397 10.831 ;
     RECT  10.044 10.291 11.25 10.867 ;
     RECT  20.988 10.741 23.67 10.939 ;
     RECT  13.215 2.413 13.497 11.281 ;
     RECT  2.415 2.413 2.697 11.785 ;
     RECT  2.376 11.785 2.697 11.821 ;
     RECT  4.932 10.831 5.397 11.821 ;
     RECT  12.78 11.281 13.497 12.187 ;
     RECT  15.408 10.057 16.614 12.187 ;
     RECT  4.788 11.821 5.397 12.253 ;
     RECT  2.376 11.821 3.078 12.289 ;
     RECT  12.78 12.187 13.59 12.317 ;
     RECT  14.832 12.187 16.614 12.317 ;
     RECT  2.376 12.289 3.726 12.325 ;
     RECT  4.788 12.253 5.634 12.361 ;
     RECT  2.34 12.325 3.726 12.451 ;
     RECT  4.788 12.361 5.742 12.451 ;
     RECT  2.34 12.451 5.742 12.487 ;
     RECT  6.84 11.911 6.858 12.721 ;
     RECT  7.815 2.413 8.097 12.721 ;
     RECT  6.84 12.721 8.097 12.757 ;
     RECT  2.304 12.487 5.742 12.829 ;
     RECT  20.232 12.181 20.25 12.829 ;
     RECT  20.988 10.939 23.994 12.829 ;
     RECT  0.54 12.523 0.558 12.865 ;
     RECT  25.056 12.721 25.074 12.901 ;
     RECT  2.304 12.829 5.886 12.991 ;
     RECT  6.768 12.757 8.097 12.991 ;
     RECT  20.232 12.829 23.994 13.019 ;
     RECT  25.056 12.901 25.758 13.369 ;
     RECT  0.108 12.865 0.558 13.517 ;
     RECT  18.615 2.413 18.897 13.531 ;
     RECT  12.78 12.317 13.497 13.567 ;
     RECT  21.024 13.019 23.994 13.613 ;
     RECT  25.056 13.369 25.83 13.709 ;
     RECT  2.304 12.991 8.097 13.711 ;
     RECT  9.756 10.867 11.25 13.801 ;
     RECT  25.056 13.709 25.794 13.901 ;
     RECT  25.056 13.901 25.758 13.909 ;
     RECT  24.516 13.909 25.758 13.997 ;
     RECT  24.516 13.997 25.722 14.093 ;
     RECT  20.232 13.019 20.25 14.107 ;
     RECT  21.024 13.613 23.634 14.107 ;
     RECT  0.108 13.517 0.27 14.347 ;
     RECT  0.108 14.347 0.342 14.395 ;
     RECT  2.304 13.711 8.586 14.449 ;
     RECT  9.612 13.801 11.25 14.449 ;
     RECT  12.276 13.567 13.497 14.449 ;
     RECT  18.615 13.531 19.422 14.485 ;
     RECT  20.232 14.107 23.634 14.485 ;
     RECT  0.108 14.395 0.414 14.573 ;
     RECT  24.516 14.093 25.146 14.573 ;
     RECT  18.615 14.485 23.634 14.719 ;
     RECT  0.108 14.573 0.27 14.819 ;
     RECT  25.02 14.573 25.146 14.827 ;
     RECT  12.132 14.449 13.497 14.881 ;
     RECT  17.352 9.517 17.37 14.881 ;
     RECT  25.02 14.827 25.182 14.971 ;
     RECT  17.352 14.881 17.478 15.017 ;
     RECT  2.304 14.449 11.25 15.025 ;
     RECT  18.615 14.719 23.922 15.053 ;
     RECT  2.268 15.025 11.25 15.149 ;
     RECT  25.02 14.971 25.758 15.149 ;
     RECT  15.228 12.317 16.614 15.151 ;
     RECT  12.06 14.881 13.497 15.331 ;
     RECT  0.108 14.819 0.198 15.437 ;
     RECT  15.048 15.151 16.614 15.457 ;
     RECT  18.615 15.053 23.634 15.493 ;
     RECT  18.576 15.493 23.634 15.533 ;
     RECT  25.02 15.149 25.146 15.601 ;
     RECT  0.18 15.437 0.198 15.629 ;
     RECT  14.796 15.457 16.614 15.629 ;
     RECT  24.516 15.601 25.146 15.629 ;
     RECT  2.304 15.149 11.25 15.763 ;
     RECT  11.988 15.331 13.497 15.763 ;
     RECT  24.516 15.629 25.074 15.799 ;
     RECT  14.832 15.629 16.614 15.821 ;
     RECT  2.304 15.763 13.497 16.033 ;
     RECT  14.868 15.821 16.614 16.141 ;
     RECT  17.352 15.017 17.406 16.141 ;
     RECT  14.868 16.141 17.406 16.295 ;
     RECT  18.576 15.533 23.418 16.339 ;
     RECT  14.868 16.295 16.614 16.367 ;
     RECT  24.48 15.799 25.074 16.375 ;
     RECT  25.812 16.267 25.83 16.375 ;
     RECT  24.48 16.375 25.83 16.589 ;
     RECT  24.48 16.589 25.074 16.781 ;
     RECT  18.576 16.339 23.634 16.807 ;
     RECT  18.396 16.807 23.634 16.879 ;
     RECT  0.108 16.375 0.126 16.915 ;
     RECT  0.108 16.915 0.162 16.951 ;
     RECT  2.268 16.033 13.497 17.069 ;
     RECT  18.324 16.879 23.634 17.165 ;
     RECT  24.516 16.781 25.074 17.41 ;
     RECT  25.812 16.589 25.83 17.41 ;
     RECT  15.408 16.367 16.614 17.491 ;
     RECT  17.352 16.295 17.406 17.491 ;
     RECT  18.324 17.165 23.526 17.519 ;
     RECT  18.324 17.519 23.454 17.795 ;
     RECT  0.108 16.951 0.558 18.029 ;
     RECT  18.324 17.795 23.418 18.193 ;
     RECT  24.516 17.41 25.83 18.265 ;
     RECT  2.304 17.069 13.497 18.283 ;
     RECT  24.444 18.265 25.83 18.317 ;
     RECT  2.268 18.283 13.497 18.329 ;
     RECT  18.252 18.193 23.418 18.329 ;
     RECT  0.108 18.029 0.342 18.509 ;
     RECT  18.324 18.329 23.418 18.571 ;
     RECT  0.18 18.509 0.234 18.605 ;
     RECT  18.324 18.571 23.886 18.725 ;
     RECT  0.18 18.605 0.198 18.797 ;
     RECT  24.984 18.317 25.83 18.797 ;
     RECT  15.408 17.491 17.406 18.967 ;
     RECT  14.832 18.967 17.406 19.039 ;
     RECT  14.724 19.039 17.406 19.075 ;
     RECT  18.324 18.725 23.742 19.139 ;
     RECT  14.652 19.075 17.406 19.229 ;
     RECT  25.056 18.797 25.83 19.229 ;
     RECT  18.324 19.139 23.634 19.273 ;
     RECT  14.796 19.229 17.406 19.301 ;
     RECT  18.252 19.273 23.634 19.499 ;
     RECT  0.144 19.771 0.162 19.885 ;
     RECT  0.108 19.885 0.162 19.949 ;
     RECT  0.108 19.949 0.126 20.045 ;
     RECT  25.776 19.229 25.83 20.045 ;
     RECT  15.408 19.301 17.406 20.047 ;
     RECT  1.404 18.091 1.422 20.147 ;
     RECT  25.776 20.045 25.794 20.191 ;
     RECT  18.324 19.499 23.634 20.317 ;
     RECT  18.324 20.317 23.958 20.353 ;
     RECT  25.056 20.191 25.794 20.353 ;
     RECT  14.868 20.047 17.406 20.389 ;
     RECT  14.868 20.389 17.478 20.821 ;
     RECT  18.324 20.353 25.794 20.821 ;
     RECT  14.868 20.821 25.794 20.857 ;
     RECT  2.304 18.329 13.497 20.875 ;
     RECT  14.868 20.857 25.83 21.091 ;
     RECT  14.832 21.091 25.83 21.197 ;
     RECT  14.832 21.197 23.382 22.009 ;
     RECT  0.468 21.811 0.486 22.081 ;
     RECT  24.516 21.197 25.83 22.123 ;
     RECT  24.48 22.123 25.83 22.307 ;
     RECT  2.268 20.875 13.497 22.315 ;
     RECT  24.516 22.307 25.83 22.349 ;
     RECT  0.468 22.081 0.558 22.747 ;
     RECT  14.832 22.009 23.418 22.783 ;
     RECT  14.832 22.783 23.49 22.877 ;
     RECT  0.108 22.747 0.558 23.021 ;
     RECT  1.692 22.315 13.497 23.089 ;
     RECT  0.144 23.021 0.558 23.213 ;
     RECT  25.812 22.349 25.83 23.279 ;
     RECT  24.516 22.349 25.074 23.395 ;
     RECT  1.692 23.089 13.698 23.629 ;
     RECT  14.832 22.877 23.454 23.629 ;
     RECT  1.692 23.629 23.454 23.701 ;
     RECT  0.144 23.213 0.162 23.827 ;
     RECT  24.516 23.395 25.11 23.891 ;
     RECT  0.108 23.827 0.162 24.173 ;
     RECT  0.144 24.173 0.162 24.269 ;
     RECT  1.692 23.701 23.526 24.431 ;
     RECT  25.812 24.427 25.83 24.467 ;
     RECT  15.408 24.431 23.526 24.475 ;
     RECT  15.408 24.475 23.634 24.653 ;
     RECT  1.692 24.431 14.274 24.763 ;
     RECT  1.152 24.763 14.274 24.773 ;
     RECT  15.408 24.653 23.13 24.809 ;
     RECT  0.216 24.331 0.342 25.051 ;
     RECT  0.18 25.051 0.342 25.096 ;
     RECT  24.516 23.891 25.074 25.099 ;
     RECT  0.108 25.096 0.342 25.229 ;
     RECT  24.012 25.099 25.074 25.349 ;
     RECT  2.268 24.773 14.274 25.439 ;
     RECT  24.48 25.349 25.074 25.619 ;
     RECT  15.408 24.809 23.094 25.681 ;
     RECT  24.516 25.619 25.074 25.753 ;
     RECT  25.812 25.387 25.83 25.753 ;
     RECT  15.408 25.681 23.238 25.771 ;
     RECT  2.268 25.439 13.698 25.987 ;
     RECT  15.408 25.771 23.454 25.987 ;
     RECT  0.144 25.229 0.162 26.045 ;
     RECT  24.516 25.753 25.83 26.087 ;
     RECT  2.196 25.987 13.698 26.093 ;
     RECT  14.868 25.987 23.454 26.131 ;
     RECT  14.868 26.131 23.562 26.357 ;
     RECT  14.868 26.357 17.37 26.365 ;
     RECT  2.268 26.093 13.698 26.519 ;
     RECT  0.324 26.443 0.342 26.573 ;
     RECT  24.984 26.087 25.83 26.663 ;
     RECT  1.152 24.773 1.17 26.861 ;
     RECT  18.18 26.357 23.562 26.869 ;
     RECT  2.268 26.519 13.497 26.905 ;
     RECT  18.18 26.869 23.958 27.115 ;
     RECT  18.18 27.115 24.174 27.211 ;
     RECT  24.984 26.663 25.722 27.211 ;
     RECT  14.832 26.365 17.37 27.301 ;
     RECT  18.18 27.211 25.722 27.301 ;
     RECT  0.54 27.211 0.558 27.337 ;
     RECT  0.108 27.337 0.558 27.437 ;
     RECT  2.232 26.905 13.497 27.437 ;
     RECT  14.832 27.301 25.722 27.869 ;
     RECT  23.94 27.869 25.722 27.985 ;
     RECT  23.94 27.985 25.758 28.109 ;
     RECT  14.832 27.869 23.13 28.139 ;
     RECT  2.304 27.437 13.497 28.555 ;
     RECT  2.268 28.555 13.497 28.651 ;
     RECT  15.48 28.139 23.13 28.651 ;
     RECT  2.232 28.651 13.497 28.715 ;
     RECT  0.54 27.437 0.558 28.795 ;
     RECT  23.94 28.109 25.11 28.823 ;
     RECT  24.444 28.823 25.11 28.843 ;
     RECT  0.108 28.795 0.558 28.877 ;
     RECT  15.48 28.651 23.202 28.921 ;
     RECT  15.48 28.921 23.49 29.029 ;
     RECT  15.408 29.029 23.49 29.065 ;
     RECT  24.444 28.843 25.83 29.129 ;
     RECT  14.868 29.065 23.49 29.227 ;
     RECT  0.108 28.877 0.126 29.453 ;
     RECT  24.444 29.129 25.794 29.561 ;
     RECT  14.832 29.227 23.49 29.903 ;
     RECT  24.444 29.561 25.11 29.939 ;
     RECT  0.324 29.995 0.342 30.073 ;
     RECT  0.324 30.073 0.558 30.181 ;
     RECT  14.868 29.903 23.49 30.271 ;
     RECT  1.296 28.267 1.314 30.407 ;
     RECT  24.48 29.939 25.11 30.415 ;
     RECT  2.268 28.715 13.497 30.443 ;
     RECT  0.108 30.181 0.558 30.701 ;
     RECT  24.48 30.415 25.146 30.713 ;
     RECT  24.516 30.713 25.146 30.763 ;
     RECT  0.108 30.701 0.342 30.797 ;
     RECT  14.868 30.271 23.562 30.847 ;
     RECT  14.724 30.847 23.562 31.019 ;
     RECT  0.144 30.797 0.342 31.181 ;
     RECT  24.516 30.763 25.758 31.217 ;
     RECT  2.304 30.443 13.497 31.243 ;
     RECT  18.324 31.019 23.562 31.379 ;
     RECT  24.516 31.217 25.074 31.72 ;
     RECT  24.48 31.72 25.074 31.757 ;
     RECT  15.408 31.019 17.37 31.801 ;
     RECT  14.76 31.801 17.37 31.919 ;
     RECT  2.268 31.243 13.497 31.991 ;
     RECT  24.984 31.757 25.074 31.999 ;
     RECT  25.812 31.243 25.83 31.999 ;
     RECT  0.144 31.181 0.162 32.035 ;
     RECT  0.108 32.035 0.162 32.341 ;
     RECT  18.324 31.379 23.418 32.341 ;
     RECT  24.984 31.999 25.83 32.611 ;
     RECT  18.324 32.341 23.49 32.701 ;
     RECT  24.516 32.611 25.83 32.701 ;
     RECT  18.324 32.701 25.83 32.729 ;
     RECT  2.304 31.991 13.497 32.737 ;
     RECT  18.615 32.729 25.83 33.005 ;
     RECT  18.615 33.005 23.49 33.071 ;
     RECT  0.108 32.341 0.558 33.101 ;
     RECT  2.268 32.737 13.497 33.307 ;
     RECT  15.408 31.919 17.37 33.377 ;
     RECT  2.16 33.307 13.497 33.581 ;
     RECT  0.108 33.101 0.162 33.677 ;
     RECT  0.144 33.677 0.162 33.773 ;
     RECT  24.48 33.005 25.83 34.027 ;
     RECT  0.18 33.853 0.198 34.315 ;
     RECT  18.615 33.071 23.454 34.393 ;
     RECT  24.444 34.027 25.83 34.411 ;
     RECT  18.615 34.393 23.49 34.501 ;
     RECT  2.304 33.581 13.497 34.507 ;
     RECT  18.615 34.501 23.562 34.591 ;
     RECT  24.408 34.411 25.83 34.591 ;
     RECT  2.232 34.507 13.497 34.655 ;
     RECT  0.18 34.315 0.342 34.733 ;
     RECT  18.615 34.591 25.83 34.925 ;
     RECT  15.408 33.377 16.614 35.131 ;
     RECT  25.812 34.925 25.83 35.159 ;
     RECT  14.832 35.131 16.614 35.239 ;
     RECT  17.352 33.377 17.37 35.239 ;
     RECT  14.832 35.239 17.37 35.261 ;
     RECT  2.304 34.655 13.497 35.515 ;
     RECT  15.408 35.261 17.37 35.537 ;
     RECT  0.144 35.371 0.162 35.741 ;
     RECT  18.615 34.925 24.498 35.743 ;
     RECT  2.232 35.515 13.497 35.969 ;
     RECT  17.352 35.537 17.37 35.969 ;
     RECT  14.256 35.401 14.274 36.077 ;
     RECT  15.408 35.537 16.578 36.085 ;
     RECT  2.232 35.969 12.294 36.509 ;
     RECT  17.676 36.247 17.694 36.553 ;
     RECT  15.192 36.085 16.578 36.751 ;
     RECT  0.324 36.715 0.342 36.811 ;
     RECT  14.796 36.751 16.578 36.815 ;
     RECT  0.18 36.811 0.342 36.845 ;
     RECT  13.032 35.969 13.497 36.851 ;
     RECT  14.796 36.815 14.85 36.851 ;
     RECT  14.832 36.851 14.85 36.893 ;
     RECT  2.232 36.509 12.15 36.923 ;
     RECT  0.18 36.845 0.27 36.931 ;
     RECT  0.108 36.931 0.27 36.959 ;
     RECT  2.232 36.923 11.754 37.319 ;
     RECT  17.676 36.553 17.73 37.319 ;
     RECT  18.615 35.743 25.074 37.589 ;
     RECT  0.108 36.959 0.234 37.597 ;
     RECT  1.152 35.851 1.17 37.675 ;
     RECT  0.072 37.597 0.234 37.771 ;
     RECT  0.072 37.771 0.342 37.901 ;
     RECT  25.812 37.867 25.83 37.903 ;
     RECT  25.812 37.903 25.902 37.931 ;
     RECT  1.152 37.675 1.458 38.011 ;
     RECT  2.232 37.319 7.074 38.011 ;
     RECT  17.712 37.319 17.73 38.039 ;
     RECT  1.152 38.011 7.074 38.101 ;
     RECT  7.815 37.319 11.754 38.101 ;
     RECT  20.7 37.589 25.074 38.129 ;
     RECT  1.152 38.101 11.754 38.165 ;
     RECT  0.072 37.901 0.162 38.189 ;
     RECT  1.404 38.165 11.754 38.309 ;
     RECT  21.096 38.129 25.038 38.399 ;
     RECT  9.648 38.309 11.754 38.543 ;
     RECT  9.864 38.543 11.754 38.813 ;
     RECT  15.915 36.815 16.578 38.849 ;
     RECT  21.096 38.399 24.498 38.939 ;
     RECT  9.936 38.813 11.754 39.209 ;
     RECT  0.072 38.189 0.126 39.515 ;
     RECT  1.404 38.309 8.766 39.749 ;
     RECT  18.615 37.589 19.854 39.893 ;
     RECT  3.456 39.749 8.766 39.929 ;
     RECT  21.096 38.939 24.282 40.019 ;
     RECT  3.456 39.929 3.618 40.091 ;
     RECT  4.428 39.929 8.766 40.091 ;
     RECT  0.072 39.515 0.09 40.127 ;
     RECT  3.528 40.091 3.618 40.199 ;
     RECT  5.115 40.091 8.766 40.199 ;
     RECT  10.008 39.209 11.754 40.199 ;
     RECT  3.6 40.199 3.618 40.289 ;
     RECT  18.615 39.893 18.954 40.469 ;
     RECT  25.884 37.931 25.902 40.559 ;
     RECT  1.404 39.749 2.697 40.595 ;
     RECT  21.168 40.019 24.282 40.703 ;
     RECT  7.2 40.199 8.766 40.829 ;
     RECT  21.168 40.703 24.21 40.829 ;
     RECT  1.404 40.595 1.422 40.865 ;
     RECT  5.115 40.199 6.066 41.171 ;
     RECT  10.515 40.199 11.754 41.207 ;
     RECT  18.615 40.469 18.897 41.251 ;
     RECT  7.815 40.829 8.766 41.279 ;
     RECT  18.615 41.251 18.954 41.441 ;
     RECT  21.168 40.829 23.706 41.549 ;
     RECT  19.836 39.893 19.854 41.639 ;
     RECT  21.168 41.549 23.598 41.819 ;
     RECT  5.115 41.171 5.742 41.909 ;
     RECT  21.315 41.819 23.598 41.909 ;
     RECT  21.315 41.909 23.562 42.089 ;
     RECT  11.736 41.207 11.754 42.179 ;
     RECT  21.315 42.089 22.734 42.179 ;
     RECT  22.716 42.179 22.734 42.449 ;
     RECT  23.544 42.089 23.562 42.449 ;
     RECT  2.415 40.595 2.697 49.427 ;
     RECT  5.115 41.909 5.397 49.427 ;
     RECT  7.815 41.279 8.097 49.427 ;
     RECT  10.515 41.207 10.797 49.427 ;
     RECT  13.215 36.851 13.497 49.427 ;
     RECT  15.915 38.849 16.197 49.427 ;
     RECT  18.615 41.441 18.897 49.427 ;
     RECT  21.315 42.179 21.597 49.427 ;
     RECT  2.415 49.427 2.505 49.697 ;
     RECT  5.115 49.427 5.205 49.697 ;
     RECT  7.815 49.427 7.905 49.697 ;
     RECT  10.515 49.427 10.605 49.697 ;
     RECT  13.215 49.427 13.305 49.697 ;
     RECT  15.915 49.427 16.005 49.697 ;
     RECT  18.615 49.427 18.705 49.697 ;
     RECT  21.315 49.427 21.405 49.697 ;
    LAYER M4 ;
     RECT  0.06 13.488 0.569 38.76 ;
     RECT  0.569 13.584 2.408 38.76 ;
     RECT  2.408 2.148 2.512 49.692 ;
     RECT  2.512 2.418 2.704 49.422 ;
     RECT  2.704 13.584 2.765 38.472 ;
     RECT  2.765 19.776 2.837 38.472 ;
     RECT  2.837 21.936 2.873 31.896 ;
     RECT  2.873 21.936 2.909 24.216 ;
     RECT  2.873 27.696 2.909 31.896 ;
     RECT  2.837 33.024 2.981 38.472 ;
     RECT  2.909 27.888 3.017 31.896 ;
     RECT  2.837 19.776 3.089 20.712 ;
     RECT  3.017 27.888 3.125 28.488 ;
     RECT  3.017 29.76 3.125 31.896 ;
     RECT  2.909 24.192 3.197 24.216 ;
     RECT  2.981 33.024 3.197 38.232 ;
     RECT  3.089 19.824 3.233 20.712 ;
     RECT  2.909 21.936 3.233 22.824 ;
     RECT  2.873 25.2 3.305 26.664 ;
     RECT  3.197 34.416 3.305 38.232 ;
     RECT  3.305 34.416 3.341 34.44 ;
     RECT  3.305 25.2 3.377 26.568 ;
     RECT  2.765 13.632 3.413 16.392 ;
     RECT  3.413 15.12 3.443 16.392 ;
     RECT  3.305 35.568 3.521 38.232 ;
     RECT  3.125 27.888 3.629 27.912 ;
     RECT  3.443 15.456 3.665 16.392 ;
     RECT  2.765 17.424 3.769 18.504 ;
     RECT  3.665 16.224 3.805 16.392 ;
     RECT  3.769 17.424 3.805 18.744 ;
     RECT  3.805 16.224 3.917 18.744 ;
     RECT  3.917 16.272 3.989 18.744 ;
     RECT  3.521 36.912 3.997 38.232 ;
     RECT  3.997 36.912 4.025 37.512 ;
     RECT  3.377 25.2 4.129 25.8 ;
     RECT  4.021 39.216 4.129 39.24 ;
     RECT  3.197 33.024 4.165 33.048 ;
     RECT  3.989 18.72 4.309 18.744 ;
     RECT  3.233 21.936 4.309 22.2 ;
     RECT  3.125 29.76 4.453 29.832 ;
     RECT  4.165 33.024 4.453 33.096 ;
     RECT  3.521 35.568 4.453 35.928 ;
     RECT  4.453 33.024 4.489 33.576 ;
     RECT  4.453 34.704 4.489 35.928 ;
     RECT  4.129 25.104 4.525 25.8 ;
     RECT  3.125 30.864 4.525 31.896 ;
     RECT  4.525 25.008 4.813 25.8 ;
     RECT  3.233 20.4 4.837 20.712 ;
     RECT  4.309 21.696 4.837 22.2 ;
     RECT  4.837 20.4 4.885 22.2 ;
     RECT  4.813 25.008 4.885 26.232 ;
     RECT  4.129 39.216 4.913 39.288 ;
     RECT  4.525 15.216 4.933 15.24 ;
     RECT  3.989 16.272 4.933 17.448 ;
     RECT  3.413 13.632 4.957 14.088 ;
     RECT  4.933 15.216 4.957 17.448 ;
     RECT  4.309 18.72 4.957 18.84 ;
     RECT  4.885 25.008 4.957 27.096 ;
     RECT  4.849 23.616 4.993 23.64 ;
     RECT  4.957 18.48 5.029 18.84 ;
     RECT  4.885 20.16 5.029 22.2 ;
     RECT  4.993 23.616 5.029 23.976 ;
     RECT  5.029 18.48 5.065 22.2 ;
     RECT  5.029 23.568 5.065 23.976 ;
     RECT  4.957 25.008 5.101 27.624 ;
     RECT  4.957 13.632 5.108 17.448 ;
     RECT  5.065 18.48 5.108 23.976 ;
     RECT  5.101 25.008 5.108 27.72 ;
     RECT  4.453 29.568 5.108 29.832 ;
     RECT  4.525 30.864 5.108 31.992 ;
     RECT  4.489 33.024 5.108 35.928 ;
     RECT  4.025 36.912 5.108 36.936 ;
     RECT  4.913 38.784 5.108 39.288 ;
     RECT  5.108 2.148 5.212 49.692 ;
     RECT  5.212 2.418 5.404 49.422 ;
     RECT  5.404 33.024 5.465 37.656 ;
     RECT  5.404 26.784 5.537 28.008 ;
     RECT  5.537 26.784 5.645 27.912 ;
     RECT  5.404 29.472 5.645 31.992 ;
     RECT  5.465 33.024 5.717 35.592 ;
     RECT  5.404 38.784 5.717 39.24 ;
     RECT  5.404 13.632 5.753 13.848 ;
     RECT  5.717 34.704 5.753 35.592 ;
     RECT  5.717 39.216 5.825 39.24 ;
     RECT  5.465 36.768 5.987 37.656 ;
     RECT  5.753 34.752 6.028 35.592 ;
     RECT  5.717 33.024 6.149 33.336 ;
     RECT  6.028 34.752 6.149 34.776 ;
     RECT  5.404 17.04 6.469 25.8 ;
     RECT  5.404 14.928 6.541 16.008 ;
     RECT  6.149 33.312 6.793 33.336 ;
     RECT  6.541 14.784 6.829 16.008 ;
     RECT  6.469 17.04 6.829 25.992 ;
     RECT  5.645 27.072 6.829 27.912 ;
     RECT  5.987 36.768 6.829 37.08 ;
     RECT  5.645 29.472 6.833 31.704 ;
     RECT  6.829 17.04 6.901 27.912 ;
     RECT  6.829 14.64 7.261 16.008 ;
     RECT  6.901 17.04 7.261 28.488 ;
     RECT  6.833 30.576 7.369 31.704 ;
     RECT  6.793 33.312 7.369 34.2 ;
     RECT  7.369 30.576 7.621 34.2 ;
     RECT  5.753 13.632 7.808 13.656 ;
     RECT  7.261 14.64 7.808 28.488 ;
     RECT  6.833 29.472 7.808 29.496 ;
     RECT  7.621 30.576 7.808 34.248 ;
     RECT  6.829 35.808 7.808 37.08 ;
     RECT  7.808 2.148 7.912 49.692 ;
     RECT  7.912 2.418 8.104 49.422 ;
     RECT  8.104 33.552 8.129 33.576 ;
     RECT  8.104 16.368 8.165 19.56 ;
     RECT  8.104 30.288 8.201 31.224 ;
     RECT  8.104 26.256 8.243 29.208 ;
     RECT  8.201 30.288 8.243 30.648 ;
     RECT  8.104 21.12 8.273 21.72 ;
     RECT  8.273 21.456 8.309 21.72 ;
     RECT  8.104 35.04 8.339 37.08 ;
     RECT  8.165 16.368 8.345 19.032 ;
     RECT  8.104 22.8 8.381 24.12 ;
     RECT  8.243 29.184 8.381 29.208 ;
     RECT  8.339 36.384 8.381 37.08 ;
     RECT  8.309 21.456 8.561 21.48 ;
     RECT  8.381 36.912 9.001 37.08 ;
     RECT  8.345 17.568 9.137 19.032 ;
     RECT  8.243 26.256 9.205 27.912 ;
     RECT  8.104 14.784 9.253 15.336 ;
     RECT  8.345 16.368 9.253 16.392 ;
     RECT  9.001 36.912 9.317 36.936 ;
     RECT  9.241 33.648 9.325 33.672 ;
     RECT  8.381 22.8 9.347 23.352 ;
     RECT  9.137 18.144 9.349 19.032 ;
     RECT  9.205 26.256 9.353 28.008 ;
     RECT  9.353 26.256 9.389 26.808 ;
     RECT  9.347 23.088 9.461 23.352 ;
     RECT  9.241 24.912 10.141 24.936 ;
     RECT  9.389 26.256 10.141 26.76 ;
     RECT  9.253 14.784 10.357 16.392 ;
     RECT  9.529 32.592 10.357 32.616 ;
     RECT  9.997 35.904 10.357 35.928 ;
     RECT  10.357 35.904 10.465 36.888 ;
     RECT  10.321 37.872 10.465 37.896 ;
     RECT  10.021 12.288 10.508 12.312 ;
     RECT  10.357 14.784 10.508 16.68 ;
     RECT  9.349 18.144 10.508 19.272 ;
     RECT  9.277 21.12 10.508 21.144 ;
     RECT  9.461 23.328 10.508 23.352 ;
     RECT  10.141 24.912 10.508 26.76 ;
     RECT  9.673 28.464 10.508 28.488 ;
     RECT  9.601 31.104 10.508 31.128 ;
     RECT  10.357 32.592 10.508 33.144 ;
     RECT  10.465 35.904 10.508 37.896 ;
     RECT  10.508 2.148 10.612 49.692 ;
     RECT  10.612 2.418 10.804 49.422 ;
     RECT  10.804 14.832 10.829 16.68 ;
     RECT  10.829 14.832 10.973 16.392 ;
     RECT  10.973 14.832 11.081 15.816 ;
     RECT  10.804 18.144 11.801 19.416 ;
     RECT  10.804 12.288 13.208 12.312 ;
     RECT  11.081 14.928 13.208 15.816 ;
     RECT  11.801 18.144 13.208 19.272 ;
     RECT  10.804 20.592 13.208 21.144 ;
     RECT  10.804 22.464 13.208 22.536 ;
     RECT  10.804 23.568 13.208 26.616 ;
     RECT  10.804 28.416 13.208 28.488 ;
     RECT  10.804 31.104 13.208 31.128 ;
     RECT  10.804 35.136 13.208 35.16 ;
     RECT  10.804 36.864 13.208 37.896 ;
     RECT  13.208 2.148 13.312 49.692 ;
     RECT  13.312 2.418 13.504 49.422 ;
     RECT  13.504 12.192 13.601 12.312 ;
     RECT  13.601 12.192 14.821 12.216 ;
     RECT  13.504 14.928 14.821 15.72 ;
     RECT  13.504 35.136 14.821 35.16 ;
     RECT  14.821 12.192 14.861 12.312 ;
     RECT  14.821 35.136 14.861 35.256 ;
     RECT  13.504 36.768 14.861 37.896 ;
     RECT  14.861 12.288 15.908 12.312 ;
     RECT  14.821 14.928 15.908 15.816 ;
     RECT  13.504 18.144 15.908 19.272 ;
     RECT  13.504 20.592 15.908 21.144 ;
     RECT  13.504 22.464 15.908 22.536 ;
     RECT  13.504 23.568 15.908 26.616 ;
     RECT  13.504 28.416 15.908 28.488 ;
     RECT  13.504 31.104 15.908 31.128 ;
     RECT  14.861 35.232 15.908 35.256 ;
     RECT  14.861 36.864 15.908 37.896 ;
     RECT  15.908 2.148 16.012 49.692 ;
     RECT  16.012 2.418 16.204 49.422 ;
     RECT  16.204 12.288 18.608 12.312 ;
     RECT  16.204 14.928 18.608 15.816 ;
     RECT  16.204 18.144 18.608 19.272 ;
     RECT  16.204 20.592 18.608 21.24 ;
     RECT  16.204 22.464 18.608 26.616 ;
     RECT  16.204 28.416 18.608 28.488 ;
     RECT  16.204 31.104 18.608 31.128 ;
     RECT  16.204 35.232 18.608 35.256 ;
     RECT  16.204 36.864 18.608 37.896 ;
     RECT  18.608 2.148 18.712 49.692 ;
     RECT  18.712 2.418 18.904 49.422 ;
     RECT  18.904 35.136 18.929 35.256 ;
     RECT  18.904 36.768 18.929 37.896 ;
     RECT  18.904 28.416 19.217 29.16 ;
     RECT  18.904 14.928 19.973 15.72 ;
     RECT  18.904 30.384 20.113 31.8 ;
     RECT  19.217 28.416 20.185 28.968 ;
     RECT  20.185 28.176 20.437 28.968 ;
     RECT  20.113 30.384 20.437 32.088 ;
     RECT  19.973 15.216 20.509 15.72 ;
     RECT  20.005 16.848 20.509 16.872 ;
     RECT  18.929 35.232 20.509 35.256 ;
     RECT  18.904 17.904 20.617 26.904 ;
     RECT  20.437 28.176 20.617 32.088 ;
     RECT  20.509 34.656 20.869 35.256 ;
     RECT  20.617 17.904 20.941 32.088 ;
     RECT  20.509 15.216 21.013 16.872 ;
     RECT  20.941 17.904 21.013 32.184 ;
     RECT  21.013 15.216 21.049 32.184 ;
     RECT  20.869 33.84 21.061 35.256 ;
     RECT  18.904 12.288 21.308 12.312 ;
     RECT  21.049 14.4 21.308 32.184 ;
     RECT  21.061 33.264 21.308 35.256 ;
     RECT  18.929 36.864 21.308 37.896 ;
     RECT  21.149 39.36 21.308 39.384 ;
     RECT  21.308 2.148 21.412 49.692 ;
     RECT  21.412 2.418 21.604 49.422 ;
     RECT  21.604 12.288 22.421 12.312 ;
     RECT  21.604 14.4 22.451 32.472 ;
     RECT  21.604 39.888 22.465 39.912 ;
     RECT  21.604 41.616 22.573 41.64 ;
     RECT  22.451 20.976 22.633 32.472 ;
     RECT  21.604 33.84 22.633 35.4 ;
     RECT  21.604 36.624 22.813 38.232 ;
     RECT  22.789 40.272 22.813 40.296 ;
     RECT  22.451 14.4 22.849 19.944 ;
     RECT  22.813 40.272 22.876 41.064 ;
     RECT  22.876 41.04 22.897 41.064 ;
     RECT  22.633 20.976 22.961 35.4 ;
     RECT  22.961 25.776 23.141 35.4 ;
     RECT  23.141 28.944 23.353 35.4 ;
     RECT  22.849 13.776 23.497 19.944 ;
     RECT  23.497 13.008 23.605 19.944 ;
     RECT  22.813 36.624 23.645 38.664 ;
     RECT  22.961 21.744 23.929 24.792 ;
     RECT  23.929 21.168 24.001 24.792 ;
     RECT  23.141 25.776 24.001 27.912 ;
     RECT  23.605 13.008 24.037 20.136 ;
     RECT  24.001 21.168 24.037 27.912 ;
     RECT  23.353 28.944 24.325 35.496 ;
     RECT  23.645 36.624 24.325 38.28 ;
     RECT  24.037 13.008 24.469 27.912 ;
     RECT  24.325 28.944 24.469 38.28 ;
     RECT  24.469 13.008 25.884 38.28 ;
    LAYER M5 ;
     RECT  2.4 2.137 2.52 2.151 ;
     RECT  5.1 2.137 5.22 2.151 ;
     RECT  7.8 2.137 7.92 2.151 ;
     RECT  10.5 2.137 10.62 2.151 ;
     RECT  13.2 2.137 13.32 2.151 ;
     RECT  15.9 2.137 16.02 2.151 ;
     RECT  18.6 2.137 18.72 2.151 ;
     RECT  21.3 2.137 21.42 2.151 ;
     RECT  10.5 2.151 10.812 12.277 ;
     RECT  2.4 2.151 2.712 13.621 ;
     RECT  7.8 2.151 8.112 13.621 ;
     RECT  6.864 13.621 8.112 14.675 ;
     RECT  7.8 14.675 8.112 14.773 ;
     RECT  7.8 14.773 8.952 15.301 ;
     RECT  10.032 12.277 10.812 15.301 ;
     RECT  5.1 2.151 5.412 16.165 ;
     RECT  2.4 13.621 3.432 16.259 ;
     RECT  21.3 2.151 21.612 16.693 ;
     RECT  6.576 15.973 6.6 17.315 ;
     RECT  0.144 17.461 0.168 17.651 ;
     RECT  7.8 15.301 10.812 17.653 ;
     RECT  4.944 16.165 5.412 18.133 ;
     RECT  3.936 16.501 3.96 18.275 ;
     RECT  7.68 17.653 10.812 18.275 ;
     RECT  21.168 16.693 21.612 18.805 ;
     RECT  4.944 18.133 5.64 19.765 ;
     RECT  6.624 17.605 6.648 19.765 ;
     RECT  21.072 18.805 21.612 20.053 ;
     RECT  4.944 19.765 6.648 20.099 ;
     RECT  4.944 20.099 6.312 21.205 ;
     RECT  21.072 20.053 22.44 21.299 ;
     RECT  4.944 21.205 6.552 21.397 ;
     RECT  2.4 16.259 2.712 22.549 ;
     RECT  21.12 21.299 22.44 22.597 ;
     RECT  2.304 22.549 2.856 22.739 ;
     RECT  21.12 22.597 23.208 22.787 ;
     RECT  4.848 21.397 6.552 23.653 ;
     RECT  7.8 18.275 10.812 23.653 ;
     RECT  18.6 2.151 18.912 23.893 ;
     RECT  4.848 23.653 10.812 24.131 ;
     RECT  0.144 24.181 0.168 24.467 ;
     RECT  2.4 22.739 2.856 25.811 ;
     RECT  4.848 24.131 6.552 26.243 ;
     RECT  0.144 26.533 0.168 26.723 ;
     RECT  4.944 26.243 6.552 26.725 ;
     RECT  7.8 24.131 10.812 26.725 ;
     RECT  18.6 23.893 19.656 26.915 ;
     RECT  4.944 26.725 10.812 29.507 ;
     RECT  2.4 25.811 2.712 30.037 ;
     RECT  0.144 29.941 0.168 30.131 ;
     RECT  4.944 29.507 6.552 30.275 ;
     RECT  21.12 22.787 22.44 30.661 ;
     RECT  21.072 30.661 22.44 30.803 ;
     RECT  2.4 30.037 2.856 30.899 ;
     RECT  21.12 30.803 22.44 33.253 ;
     RECT  4.944 30.275 5.64 33.541 ;
     RECT  7.632 29.507 10.812 33.683 ;
     RECT  7.632 33.683 8.952 34.259 ;
     RECT  21.072 33.253 22.44 34.355 ;
     RECT  0.144 34.405 0.168 34.595 ;
     RECT  4.464 33.541 5.64 34.741 ;
     RECT  4.464 34.741 5.976 35.939 ;
     RECT  10.032 33.683 10.812 35.939 ;
     RECT  21.12 34.355 22.44 36.853 ;
     RECT  7.8 34.259 8.952 37.091 ;
     RECT  21.12 36.853 22.872 37.091 ;
     RECT  4.944 35.939 5.976 37.667 ;
     RECT  3.936 36.901 3.96 38.243 ;
     RECT  4.944 37.667 5.412 38.819 ;
     RECT  21.168 37.091 22.872 39.395 ;
     RECT  21.3 39.395 22.872 41.075 ;
     RECT  21.3 41.075 22.536 41.651 ;
     RECT  2.4 30.899 2.712 49.689 ;
     RECT  5.1 38.819 5.412 49.689 ;
     RECT  7.8 37.091 8.112 49.689 ;
     RECT  10.5 35.939 10.812 49.689 ;
     RECT  13.2 2.151 13.512 49.689 ;
     RECT  15.9 2.151 16.212 49.689 ;
     RECT  18.6 26.915 18.912 49.689 ;
     RECT  21.3 41.651 21.612 49.689 ;
     RECT  2.4 49.689 2.52 49.703 ;
     RECT  5.1 49.689 5.22 49.703 ;
     RECT  7.8 49.689 7.92 49.703 ;
     RECT  10.5 49.689 10.62 49.703 ;
     RECT  13.2 49.689 13.32 49.703 ;
     RECT  15.9 49.689 16.02 49.703 ;
     RECT  18.6 49.689 18.72 49.703 ;
     RECT  21.3 49.689 21.42 49.703 ;
     RECT  5.412 13.621 6.864 14.675 ;
     RECT  5.412 14.675 7.8 15.973 ;
     RECT  8.952 14.773 10.032 15.301 ;
     RECT  5.412 15.973 6.576 17.315 ;
     RECT  6.6 15.973 7.8 17.315 ;
     RECT  3.432 16.165 4.944 16.259 ;
     RECT  2.712 16.259 4.944 16.501 ;
     RECT  2.712 16.501 3.936 18.275 ;
     RECT  3.96 16.501 4.944 18.275 ;
     RECT  5.412 17.315 7.8 17.605 ;
     RECT  5.412 17.605 6.624 18.133 ;
     RECT  6.648 17.605 7.8 17.653 ;
     RECT  6.648 17.653 7.68 18.275 ;
     RECT  5.64 18.133 6.624 19.765 ;
     RECT  6.648 18.275 7.8 20.099 ;
     RECT  6.312 20.099 7.8 21.205 ;
     RECT  6.552 21.205 7.8 23.653 ;
     RECT  19.656 23.893 21.12 26.915 ;
     RECT  6.552 24.131 7.8 26.725 ;
     RECT  6.552 29.507 7.632 30.275 ;
     RECT  8.952 33.683 10.032 35.939 ;
     RECT  4.464 35.939 4.944 36.901 ;
     RECT  2.712 36.901 3.936 38.243 ;
     RECT  3.96 36.901 4.944 38.243 ;
  END
END qvm_data256_native
END LIBRARY
